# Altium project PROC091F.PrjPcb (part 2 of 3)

## Sheet PROC091F_HD_CONN_PWR_SW.SchDoc: BREAKAWAY_60PIN_CONN
size 431 x 279 mm; Date: Not shown in title block; ApprovedBy: Not shown in title block; CheckedBy: Not shown in title block; Author: Not shown in title block; CompanyName: Not shown in title block; DrawnBy: Antony/Bala; Engineer: Not shown in title block; Organization: Not shown in title block; Address1: Not shown in title block; Address2: Not shown in title block; Address3: Not shown in title block; Address4: Not shown in title block; DocumentNumber: 7; Revision: Use project parameter SCH_Rev; SheetNumber: 7; SheetTotal: 12; PageSetup: Record=PageOptions¦CenterHorizontal=True¦CenterVertical=True¦PrintScale=1.00¦XCorrection=1.00¦YCorrection=1.00¦PrintKind=0¦BorderSize=5000000¦LeftOffset=0¦BottomOffset=0¦Orientation=2¦PaperLength=1000¦PaperWidth=1000¦Scale=100¦PaperSource=15¦PrintQuality=600¦MediaType=1¦DitherType=10¦PaperKind=Letter¦PrintScaleMode=1

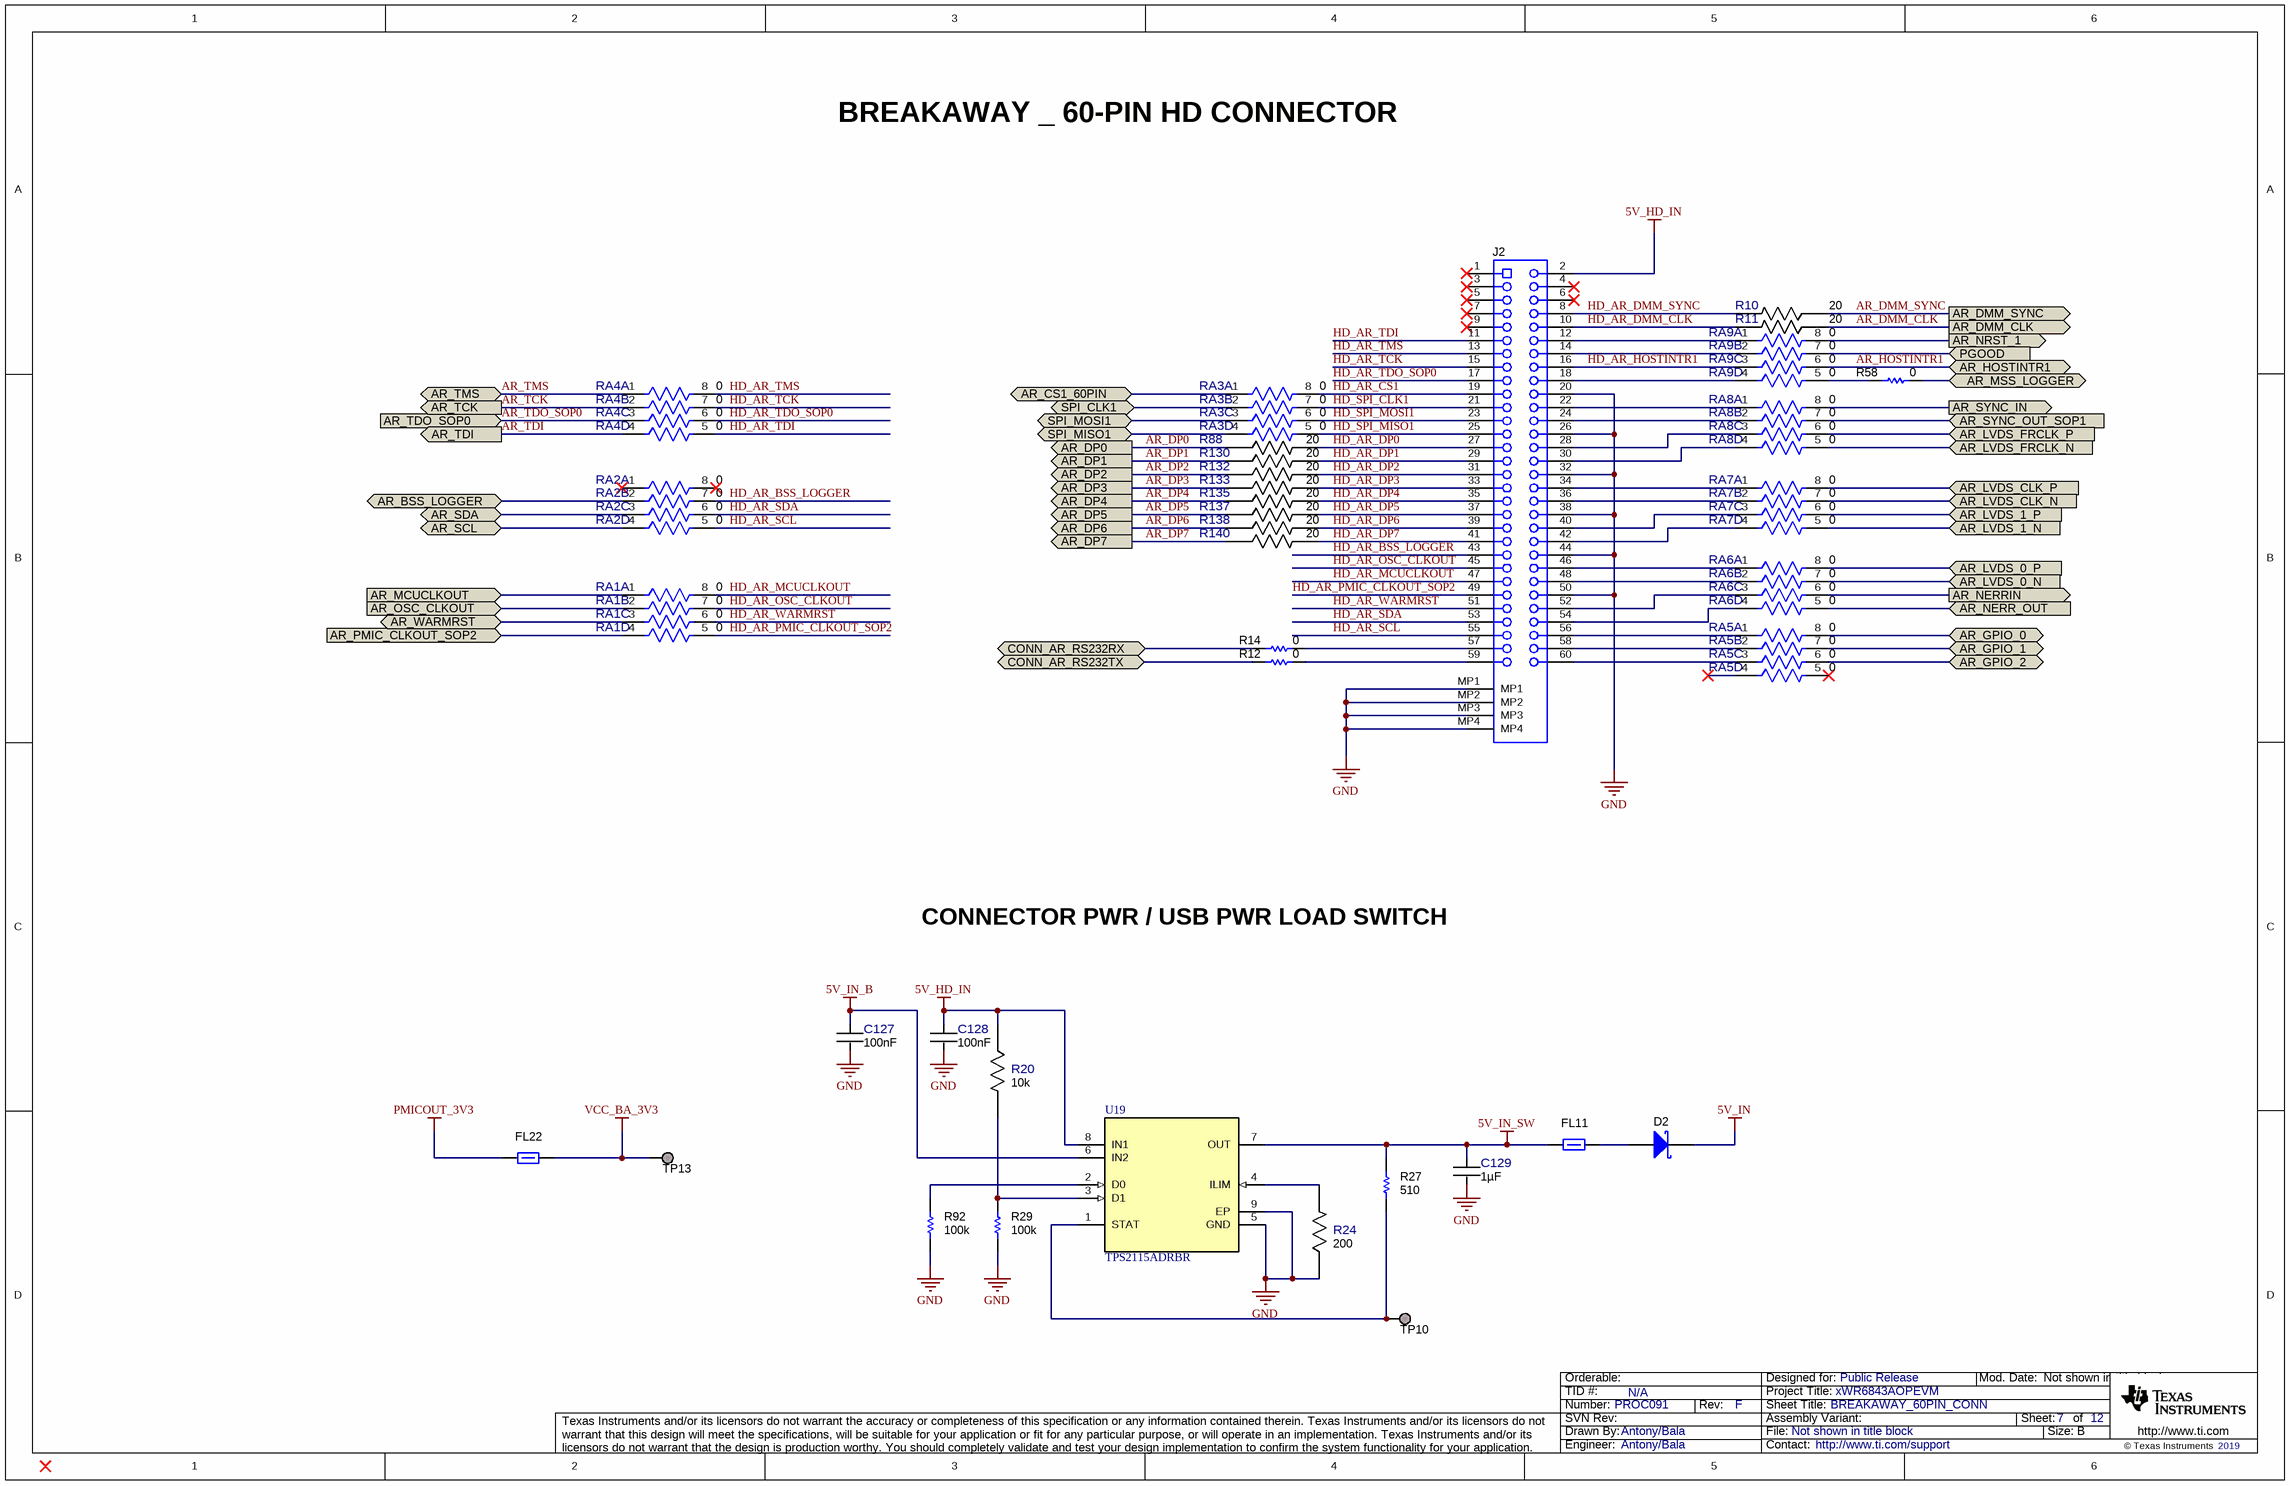
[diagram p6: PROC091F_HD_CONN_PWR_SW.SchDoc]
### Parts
C127  Cap_F: 100nF  [FP-GRM033R6YA104KE14D_0201 (0603 Metric)-IPC_C]  (hidden comment: GRM033R6YA104KE14D)
C128  Cap_F: 100nF  [FP-GRM033R6YA104KE14D_0201 (0603 Metric)-IPC_C]  (hidden comment: GRM033R6YA104KE14D)
C129  Cap_F: 1µF  [FP-CL03A105MO3NRNH_0201-IPC_C]  (hidden comment: CL03A105MO3NRNH)
D2  NSR20F30NXT5G  [DSN2_0603]  (value not drawn)
FL11  BLM15PD300SZ1D  [0402L]  (value not drawn)
FL22  BLM15PD300SZ1D  [0402L]  (value not drawn)
J2  QSH-030-01-L-D-A  [Samtec_QSH-030-01-X-D-A]  (value not drawn)
R10  Res_ohm: 20  [FP-AC0201FR-0720RL_0201-IPC_C]  (hidden comment: AC0201FR-0720RL)
R11  Res_ohm: 20  [FP-AC0201FR-0720RL_0201-IPC_C]  (hidden comment: AC0201FR-0720RL)
R12  Res_ohm: 0  [FP-RC0201JR-070RL_0201 (0603 Metric)-MFG]  (hidden comment: RC0201JR-070RL)
R14  Res_ohm: 0  [FP-RC0201JR-070RL_0201 (0603 Metric)-MFG]  (hidden comment: RC0201JR-070RL)
R20  Res_ohm: 10k  [FP-RR0306P-103-D_0201-IPC_C]  (hidden comment: RR0306P-103-D)
R24  Res_ohm: 200  [FP-CRCW0402200RFKEDHP_0402-IPC_C]  (hidden comment: CRCW0402200RFKEDHP)
R27  value 510  [0201L]  (hidden comment: RC0201JR-07510RL)
R29  value 100k  [0201L]  (hidden comment: CRCW0201100KFKED)
R58  Res_ohm: 0  [FP-RC0201JR-070RL_0201 (0603 Metric)-MFG]  (hidden comment: RC0201JR-070RL)
R88  Res_ohm: 20  [FP-AC0201FR-0720RL_0201-IPC_C]  (hidden comment: AC0201FR-0720RL)
R92  value 100k  [0201L]  (hidden comment: CRCW0201100KFKED)
R130  Res_ohm: 20  [FP-AC0201FR-0720RL_0201-IPC_C]  (hidden comment: AC0201FR-0720RL)
R132  Res_ohm: 20  [FP-AC0201FR-0720RL_0201-IPC_C]  (hidden comment: AC0201FR-0720RL)
R133  Res_ohm: 20  [FP-AC0201FR-0720RL_0201-IPC_C]  (hidden comment: AC0201FR-0720RL)
R135  Res_ohm: 20  [FP-AC0201FR-0720RL_0201-IPC_C]  (hidden comment: AC0201FR-0720RL)
R137  Res_ohm: 20  [FP-AC0201FR-0720RL_0201-IPC_C]  (hidden comment: AC0201FR-0720RL)
R138  Res_ohm: 20  [FP-AC0201FR-0720RL_0201-IPC_C]  (hidden comment: AC0201FR-0720RL)
R140  Res_ohm: 20  [FP-AC0201FR-0720RL_0201-IPC_C]  (hidden comment: AC0201FR-0720RL)
RA1  Res_ohm: 0  [FP-EXB-18VR000X_0502-MFG]  (hidden comment: EXB-18VR000X)  (parts A,B,C,D of 4)
RA2  Res_ohm: 0  [FP-EXB-18VR000X_0502-MFG]  (hidden comment: EXB-18VR000X)  (parts A,B,C,D of 4)
RA3  Res_ohm: 0  [FP-EXB-18VR000X_0502-MFG]  (hidden comment: EXB-18VR000X)  (parts A,B,C,D of 4)
RA4  Res_ohm: 0  [FP-EXB-18VR000X_0502-MFG]  (hidden comment: EXB-18VR000X)  (parts A,B,C,D of 4)
RA5  Res_ohm: 0  [FP-EXB-18VR000X_0502-MFG]  (hidden comment: EXB-18VR000X)  (parts A,B,C,D of 4)
RA6  Res_ohm: 0  [FP-EXB-18VR000X_0502-MFG]  (hidden comment: EXB-18VR000X)  (parts A,B,C,D of 4)
RA7  Res_ohm: 0  [FP-EXB-18VR000X_0502-MFG]  (hidden comment: EXB-18VR000X)  (parts A,B,C,D of 4)
RA8  Res_ohm: 0  [FP-EXB-18VR000X_0502-MFG]  (hidden comment: EXB-18VR000X)  (parts A,B,C,D of 4)
RA9  Res_ohm: 0  [FP-EXB-18VR000X_0502-MFG]  (hidden comment: EXB-18VR000X)  (parts A,B,C,D of 4)
TP10  TESTPOINT  [TP_25MIL-SMT]  (value not drawn)  (no BOM)
TP13  TESTPOINT  [TP_25MIL-SMT]  (value not drawn)  (no BOM)
U19  TPS2115ADRBR  [DRB0008B]

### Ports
AR_BSS_LOGGER (bidir), AR_CS1_60PIN (bidir), AR_DMM_CLK (out), AR_DMM_SYNC (out), AR_DP0 (out), AR_DP1 (out), AR_DP2 (out), AR_DP3 (out), AR_DP4 (out), AR_DP5 (out), AR_DP6 (out), AR_DP7 (out), AR_GPIO_0 (bidir), AR_GPIO_1 (bidir), AR_GPIO_2 (bidir), AR_HOSTINTR1 (bidir), AR_LVDS_0_N (in), AR_LVDS_0_P (in), AR_LVDS_1_N (in), AR_LVDS_1_P (in), AR_LVDS_CLK_N (in), AR_LVDS_CLK_P (in), AR_LVDS_FRCLK_N (in), AR_LVDS_FRCLK_P (in), AR_MCUCLKOUT (in), AR_MSS_LOGGER (bidir), AR_NERR_OUT (in), AR_NERRIN (out), AR_NRST_1 (out), AR_OSC_CLKOUT (in), AR_PMIC_CLKOUT_SOP2 (in), AR_SCL (bidir), AR_SDA (bidir), AR_SYNC_IN (out), AR_SYNC_OUT_SOP1 (in), AR_TCK (out), AR_TDI (out), AR_TDO_SOP0 (in), AR_TMS (bidir), AR_WARMRST (bidir), CONN_AR_RS232RX (bidir), CONN_AR_RS232TX (bidir), PGOOD (in), SPI_CLK1 (bidir), SPI_MISO1 (bidir), SPI_MOSI1 (bidir)

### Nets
5V_HD_IN: C128.1 J2.2 R20.1 U19.8(IN1)
5V_IN: D2.1(K)
5V_IN_B: C127.1 U19.6(IN2)
5V_IN_SW: C129.1 FL11.1 R27.1 U19.7(OUT)
GND: C127.2 C128.2 C129.2 J2.20 J2.26 J2.32 J2.38 J2.44 J2.50 J2.MP1 J2.MP2 J2.MP3 J2.MP4 R24.1 R29.1 R92.2 U19.5(GND) U19.9(EP)
PMICOUT_3V3: FL22.1
VCC_BA_3V3: FL22.2 TP13.1
AR_BSS_LOGGER: RA2.2 ; port AR_BSS_LOGGER
AR_CS1_60PIN: RA3.1 ; port AR_CS1_60PIN
AR_DMM_CLK: R11.1 ; port AR_DMM_CLK
AR_DMM_SYNC: R10.1 ; port AR_DMM_SYNC
AR_DP0: R88.1 ; port AR_DP0
AR_DP1: R130.1 ; port AR_DP1
AR_DP2: R132.1 ; port AR_DP2
AR_DP3: R133.1 ; port AR_DP3
AR_DP4: R135.1 ; port AR_DP4
AR_DP5: R137.1 ; port AR_DP5
AR_DP6: R138.1 ; port AR_DP6
AR_DP7: R140.1 ; port AR_DP7
AR_GPIO_0: RA5.8 ; port AR_GPIO_0
AR_GPIO_1: RA5.7 ; port AR_GPIO_1
AR_GPIO_2: RA5.6 ; port AR_GPIO_2
AR_HOSTINTR1: RA9.6 ; port AR_HOSTINTR1
AR_LVDS_0_N: RA6.7 ; port AR_LVDS_0_N
AR_LVDS_0_P: RA6.8 ; port AR_LVDS_0_P
AR_LVDS_1_N: RA7.5 ; port AR_LVDS_1_N
AR_LVDS_1_P: RA7.6 ; port AR_LVDS_1_P
AR_LVDS_CLK_N: RA7.7 ; port AR_LVDS_CLK_N
AR_LVDS_CLK_P: RA7.8 ; port AR_LVDS_CLK_P
AR_LVDS_FRCLK_N: RA8.5 ; port AR_LVDS_FRCLK_N
AR_LVDS_FRCLK_P: RA8.6 ; port AR_LVDS_FRCLK_P
AR_MCUCLKOUT: RA1.1 ; port AR_MCUCLKOUT
AR_MSS_LOGGER: R58.1 ; port AR_MSS_LOGGER
AR_NERR_OUT: RA6.5 ; port AR_NERR_OUT
AR_NERRIN: RA6.6 ; port AR_NERRIN
AR_NRST_1: RA9.8 ; port AR_NRST_1
AR_OSC_CLKOUT: RA1.2 ; port AR_OSC_CLKOUT
AR_PMIC_CLKOUT_SOP2: RA1.4 ; port AR_PMIC_CLKOUT_SOP2
AR_SCL: RA2.4 ; port AR_SCL
AR_SDA: RA2.3 ; port AR_SDA
AR_SYNC_IN: RA8.8 ; port AR_SYNC_IN
AR_SYNC_OUT_SOP1: RA8.7 ; port AR_SYNC_OUT_SOP1
AR_TCK: RA4.2 ; port AR_TCK
AR_TDI: RA4.4 ; port AR_TDI
AR_TDO_SOP0: RA4.3 ; port AR_TDO_SOP0
AR_TMS: RA4.1 ; port AR_TMS
AR_WARMRST: RA1.3 ; port AR_WARMRST
CONN_AR_RS232RX: R14.2 ; port CONN_AR_RS232RX
CONN_AR_RS232TX: R12.2 ; port CONN_AR_RS232TX
HD_AR_BSS_LOGGER: J2.43 RA2.7
HD_AR_CS1: J2.19 RA3.8
HD_AR_DMM_CLK: J2.10 R11.2
HD_AR_DMM_SYNC: J2.8 R10.2
HD_AR_DP0: J2.27 R88.2
HD_AR_DP1: J2.29 R130.2
HD_AR_DP2: J2.31 R132.2
HD_AR_DP3: J2.33 R133.2
HD_AR_DP4: J2.35 R135.2
HD_AR_DP5: J2.37 R137.2
HD_AR_DP6: J2.39 R138.2
HD_AR_DP7: J2.41 R140.2
HD_AR_HOSTINTR1: J2.16 RA9.3
HD_AR_MCUCLKOUT: J2.47 RA1.8
HD_AR_OSC_CLKOUT: J2.45 RA1.7
HD_AR_PMIC_CLKOUT_SOP2: J2.49 RA1.5
HD_AR_SCL: J2.55 RA2.5
HD_AR_SDA: J2.53 RA2.6
HD_AR_TCK: J2.15 RA4.7
HD_AR_TDI: J2.11 RA4.5
HD_AR_TDO_SOP0: J2.17 RA4.6
HD_AR_TMS: J2.13 RA4.8
HD_AR_WARMRST: J2.51 RA1.6
HD_SPI_CLK1: J2.21 RA3.7
HD_SPI_MISO1: J2.25 RA3.5
HD_SPI_MOSI1: J2.23 RA3.6
PGOOD: RA9.7 ; port PGOOD
SPI_CLK1: RA3.2 ; port SPI_CLK1
SPI_MISO1: RA3.4 ; port SPI_MISO1
SPI_MOSI1: RA3.3 ; port SPI_MOSI1
NetD2_2: D2.2(A) FL11.2
NetJ2_12: J2.12 RA9.1
NetJ2_14: J2.14 RA9.2
NetJ2_18: J2.18 RA9.4
NetJ2_22: J2.22 RA8.1
NetJ2_24: J2.24 RA8.2
NetJ2_28: J2.28 RA8.3
NetJ2_30: J2.30 RA8.4
NetJ2_34: J2.34 RA7.1
NetJ2_36: J2.36 RA7.2
NetJ2_40: J2.40 RA7.3
NetJ2_42: J2.42 RA7.4
NetJ2_46: J2.46 RA6.1
NetJ2_48: J2.48 RA6.2
NetJ2_52: J2.52 RA6.3
NetJ2_54: J2.54 RA6.4
NetJ2_56: J2.56 RA5.1
NetJ2_57: J2.57 R14.1
NetJ2_58: J2.58 RA5.2
NetJ2_59: J2.59 R12.1
NetJ2_60: J2.60 RA5.3
NetR20_2: R20.2 R29.2 U19.3(D1)
NetR24_2: R24.2 U19.4(ILIM)
NetR27_2: R27.2 TP10.1 U19.1(STAT)
NetR58_2: R58.2 RA9.5
NetR92_1: R92.1 U19.2(D0)

Not connected (* = marked no-connect by the designer): J2 1* 3* 4* 5* 6* 7* 9*; RA2 1* 8*; RA5 4* 5*

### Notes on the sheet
- BREAKAWAY _ 60-PIN HD CONNECTOR
- CONNECTOR PWR / USB PWR LOAD SWITCH

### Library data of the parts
C127 C128 = CMP-0086440-1: Cap Ceramic 0.1uF 35V X5R 10% Pad SMD 0201 85C T/R; Manufacturer: Murata Electronics North America; AEC Qualified: No; SizeZ_mm: 0.33mm; Symbol Name: SYM-GRM033R6YA104KE14D; TempCo: 15%
C129 = CMP-0086446-1: 1µF ±20% 16V Ceramic Capacitor X5R 0201; Manufacturer: Samsung Electro-Mechanics; AEC Qualified: No; SizeZ_mm: 0.39mm; Symbol Name: SYM-CL03A105MO3NRNH; TempCo: 15%
D2 = CMP-0028829-2: Diode, Schottky, 30 V, 2 A, 2-XFDFN; Manufacturer: ON Semiconductor; Value2: 0.48V; SizeY_mm: 0.8; Value: 30V; TJmax_C: 150°C; Green_Lifecycle: Not Set; SizeAreaWB_mm2: 4.68; Value1: 2A; SizeArea_mm2: 1.28; Green_REACh: Incomplete; AEC Category: Q101; SizeZ_mm: 0.31; Vf_V: 480mV; AEC Qualified: N; SizeX_mm: 1.6
FL11 FL22 = CMP-0078934-1: Inductor, Ferrite Bead, Ferrite, 2.2 A, 0.035 ohm, AEC-Q200 Grade 1, SMD; Manufacturer: MuRata; AEC Category: Q200; AEC Grade: 1; AEC Qualified: Y; DCR_ohm: 0.035; Imax_A: 2.2A; SizeArea_mm2: 0.5; SizeAreaWB_mm2: 3; SizeZ_mm: 0.6
J2 = CMP-0075524-1: Receptacle, 0.5 mm, 30x2, Gold, TH; Manufacturer: Samtec; Pitch_mm: 0.5; Gender: Female; Green_REACh: Passed; CT: False; Shrouded: N; RowSpacing_mm: 5.73; Green_Lifecycle: Active; Row_Count: 2
R10 R11 R88 R130 R132 R133 R135 R137 R138 R140 = CMP-0087185-1: RES SMD 20 OHM 1% 1/20W 0201; Manufacturer: Yageo; AEC Grade: Grade 0; AEC Qualified: Yes; Power_W: 50mW; SizeZ_mm: 0.26mm; Symbol Name: SYM-AC0201FR-0720RL; TempCo: 200ppm/°C; VDC_V: 25V
R12 R14 R58 = CMP-0086442-2: RES SMD 0 OHM JUMPER 1/20W 0201; Manufacturer: Yageo; AEC Qualified: No; Power_W: 50mW; SizeZ_mm: 0.26mm; TempCo: 200ppm/°C; Tolerance_%: 5%; VDC_V: 25V
R20 = CMP-0088002-1: 10 kOhms ±0.5% 0.05W, 1/20W Chip Resistor 0201 (0603 Metric)  Thin Film; Manufacturer: Susumu; AEC Qualified: No; Power_W: 50mW; SizeZ_mm: 0.26mm; Symbol Name: SYM-RR0306P-103-D; TempCo: 25ppm/°C; VDC_V: 15V
R24 = CMP-0087183-1: RES SMD 200 OHM 1% 1/5W 0402; Manufacturer: Vishay Dale; AEC Grade: Grade 0; AEC Qualified: Yes; Power_W: 200mW; SizeZ_mm: 0.4mm; Symbol Name: SYM-CRCW0402200RFKEDHP; TempCo: 100ppm/°C; VDC_V: 50V
R27 = CMP-0027137-1: RES, 510, 5%, 0.05 W, 0201; Manufacturer: Yageo America; AEC Category: Q200; AEC Qualified: N; EIA_Code: E24; Power_W: 50mW; SizeArea_mm2: 0.18; SizeX_mm: 0.6; SizeY_mm: 0.3; SizeZ_mm: 0.26; TempCo: 200 ppm/C; U/M: EA; Value2: 0.05W; Value_Code: 510R; VDC_V: 25V
R29 R92 = CMP-0027261-3: RES, 100 k, 1%, 0.05 W, 0201; Manufacturer: Vishay-Dale; AEC Category: Q200; AEC Qualified: N; EIA_Code: E96; Power_W: 50mW; SizeArea_mm2: 0.18; SizeX_mm: 0.6; SizeY_mm: 0.3; SizeZ_mm: 0.26; TempCo: 100 ppm/C; Value2: 0.05W; VDC_V: 30V
RA1-RA9 = CMP-0087186-1: RES ARRAY 4 RES ZERO OHM 0502; Manufacturer: Panasonic Electronic Components; AEC Qualified: No; Power_W: 100mW; SizeZ_mm: 0.45mm; TempCo: -200/+600ppm/°C; Tolerance_%: 5%; VDC_V: 12.5V
TP10 TP13 = CMP-0078143-3: TEST POINT.  No entry in BOM.
U19 = CMP-0043358-3: Dual In / Single Out Autoswitching Power Mux, 2.8 to 5.5 V, -40 to 85 degC, 8-pin SON (DRB), Green (RoHS & no Sb/Br); Manufacturer: Texas Instruments; AEC Category: Q200; AEC Qualified: N; CompType: IC; IN1, IN2 Input Voltage(Max)(V): 5.5; IN1, IN2 Input Voltage(Min)(V): 2.8; IN1 Output Current(Max)(A): 1.25; IN1 rDS(on)(Typ)(mOhm): 84; IN2 rDS(on)(Typ)(Ohms): 0.084; Number of Inputs: 2; SizeArea_mm2: 9.0; SizeAreaWB_mm2: 16.0; SizeX_mm: 3.0; SizeZ_mm: 1.0; SubFamily: Power Multiplexer (MUX)

## Sheet PROC091F_RST_GPIOs_I2C.SchDoc: BREAKAWAY_SECTION2
size 431 x 279 mm; Date: Not shown in title block; ApprovedBy: Not shown in title block; CheckedBy: Not shown in title block; Author: Not shown in title block; CompanyName: Not shown in title block; DrawnBy: Antony/Bala; Engineer: Not shown in title block; Organization: Not shown in title block; Address1: Not shown in title block; Address2: Not shown in title block; Address3: Not shown in title block; Address4: Not shown in title block; DocumentNumber: 8; Revision: Use project parameter SCH_Rev; SheetNumber: 8; SheetTotal: 12; PageSetup: Record=PageOptions¦CenterHorizontal=True¦CenterVertical=True¦PrintScale=1.00¦XCorrection=1.00¦YCorrection=1.00¦PrintKind=0¦BorderSize=5000000¦LeftOffset=0¦BottomOffset=0¦Orientation=2¦PaperLength=1000¦PaperWidth=1000¦Scale=100¦PaperSource=15¦PrintQuality=600¦MediaType=1¦DitherType=10¦PaperKind=Letter¦PrintScaleMode=1

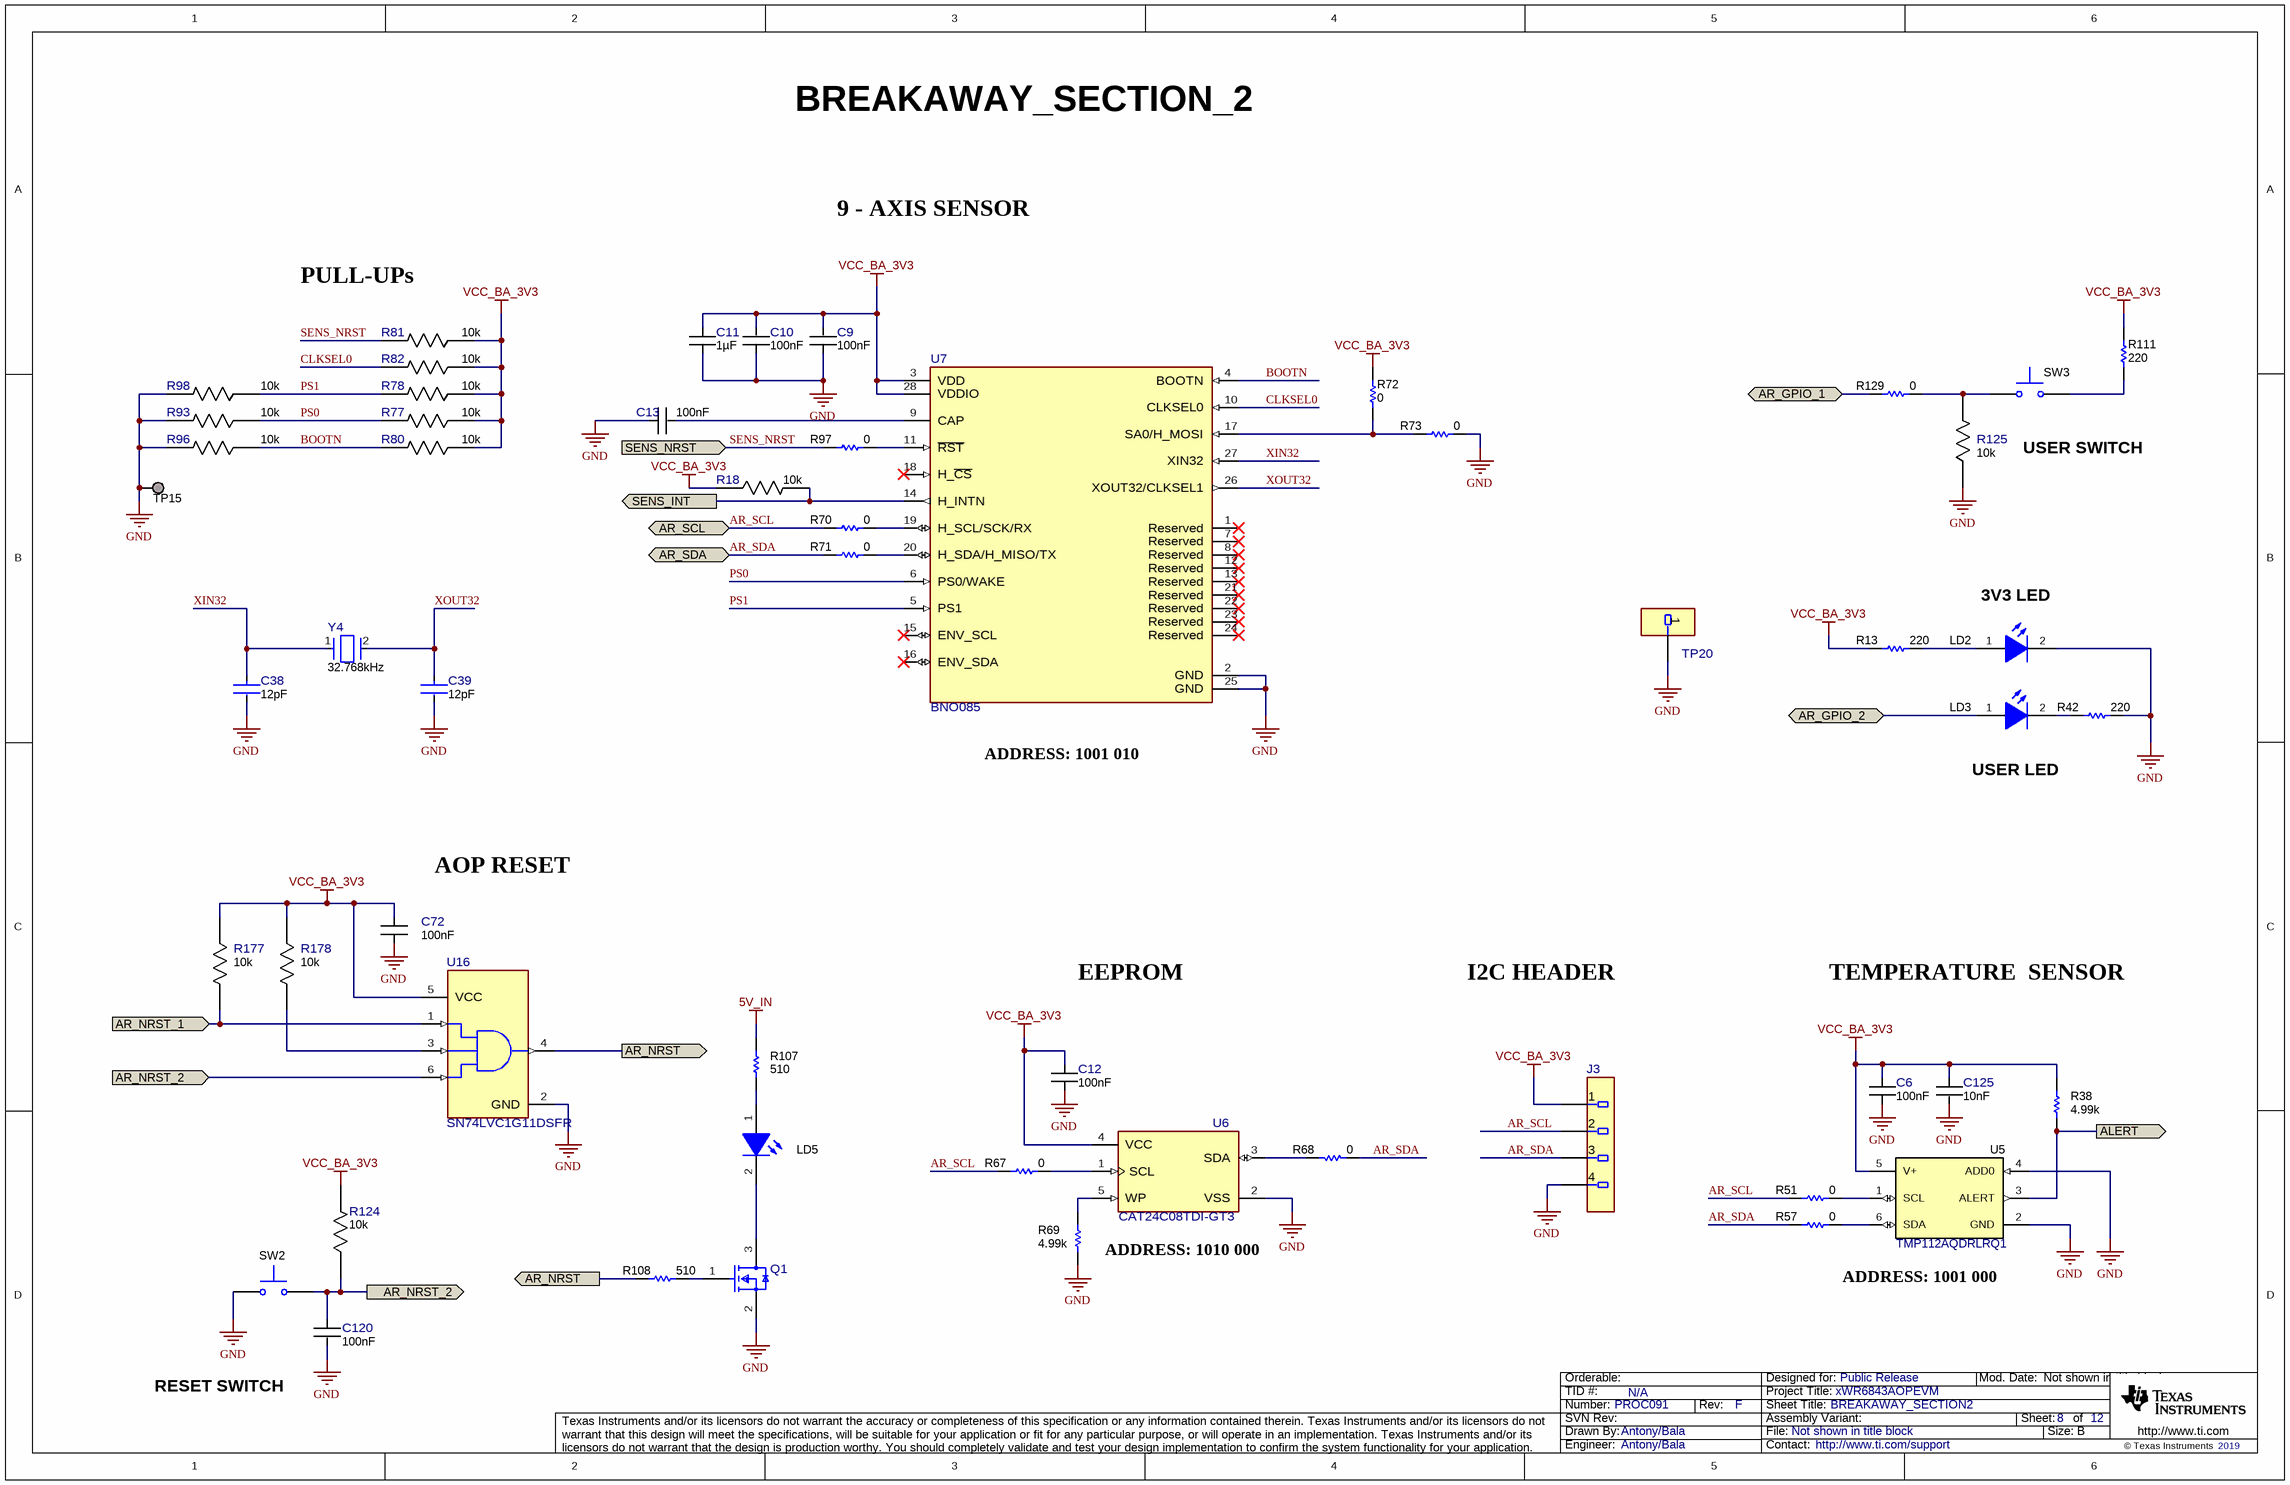
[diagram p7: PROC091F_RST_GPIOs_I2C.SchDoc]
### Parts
C6  Cap_F: 100nF  [FP-GRM033R6YA104KE14D_0201 (0603 Metric)-IPC_C]  (hidden comment: GRM033R6YA104KE14D)
C9  Cap_F: 100nF  [FP-GRM033R6YA104KE14D_0201 (0603 Metric)-IPC_C]  (hidden comment: GRM033R6YA104KE14D)
C10  Cap_F: 100nF  [FP-GRM033R6YA104KE14D_0201 (0603 Metric)-IPC_C]  (hidden comment: GRM033R6YA104KE14D)
C11  Cap_F: 1µF  [FP-CL03A105MO3NRNH_0201-IPC_C]  (hidden comment: CL03A105MO3NRNH)
C12  Cap_F: 100nF  [FP-GRM033R6YA104KE14D_0201 (0603 Metric)-IPC_C]  (hidden comment: GRM033R6YA104KE14D)
C13  Cap_F: 100nF  [FP-GRM033R6YA104KE14D_0201 (0603 Metric)-IPC_C]  (hidden comment: GRM033R6YA104KE14D)
C38  Cap_F: 12pF  [FP-250R05L120JV4T_0201-IPC_C]  (hidden comment: 250R05L120JV4T)
C39  Cap_F: 12pF  [FP-250R05L120JV4T_0201-IPC_C]  (hidden comment: 250R05L120JV4T)
C72  Cap_F: 100nF  [FP-GRM033R6YA104KE14D_0201 (0603 Metric)-IPC_C]  (hidden comment: GRM033R6YA104KE14D)
C120  Cap_F: 100nF  [FP-GRM033R6YA104KE14D_0201 (0603 Metric)-IPC_C]  (hidden comment: GRM033R6YA104KE14D)
C125  Cap_F: 10nF  [FP-CL03A103KA3NNNC_0201-IPC_C]  (hidden comment: CL03A103KA3NNNC)
J3  M50-3930442  [FP-M50-3930442_HDR4-Recommended_Land_Pattern]  (value not drawn)
LD2  APHHS1005CGCK  [APHHS1005_Green]  (value not drawn)
LD3  APHHS1005CGCK  [APHHS1005_Green]  (value not drawn)
LD5  APHHS1005CGCK  [APHHS1005_Green]  (value not drawn)
Q1  BSS123-7-F  [FP-BSS123-7-F_SOT23-IPC_C]  (value not drawn)
R13  value 220  [0201L]  (hidden comment: RC0201JR-07220RL)
R18  Res_ohm: 10k  [FP-RR0306P-103-D_0201-IPC_C]  (hidden comment: RR0306P-103-D)
R38  value 4.99k  [0201L]  (hidden comment: RC0201FR-074K99L)
R42  value 220  [0201L]  (hidden comment: RC0201JR-07220RL)
R51  Res_ohm: 0  [FP-RC0201JR-070RL_0201 (0603 Metric)-MFG]  (hidden comment: RC0201JR-070RL)
R57  Res_ohm: 0  [FP-RC0201JR-070RL_0201 (0603 Metric)-MFG]  (hidden comment: RC0201JR-070RL)
R67  Res_ohm: 0  [FP-RC0201JR-070RL_0201 (0603 Metric)-MFG]  (hidden comment: RC0201JR-070RL)
R68  Res_ohm: 0  [FP-RC0201JR-070RL_0201 (0603 Metric)-MFG]  (hidden comment: RC0201JR-070RL)
R69  value 4.99k  [0201L]  (hidden comment: RC0201FR-074K99L)
R70  Res_ohm: 0  [FP-RC0201JR-070RL_0201 (0603 Metric)-MFG]  (hidden comment: RC0201JR-070RL)
R71  Res_ohm: 0  [FP-RC0201JR-070RL_0201 (0603 Metric)-MFG]  (hidden comment: RC0201JR-070RL)
R72  Res_ohm: 0  [FP-RC0201JR-070RL_0201 (0603 Metric)-IPC_C]  (hidden comment: RC0201JR-070RL)
R73  Res_ohm: 0  [FP-RC0201JR-070RL_0201 (0603 Metric)-IPC_C]  (hidden comment: RC0201JR-070RL)
R77  Res_ohm: 10k  [FP-RR0306P-103-D_0201-IPC_C]  (hidden comment: RR0306P-103-D)
R78  Res_ohm: 10k  [FP-RR0306P-103-D_0201-IPC_C]  (hidden comment: RR0306P-103-D)
R80  Res_ohm: 10k  [FP-RR0306P-103-D_0201-IPC_C]  (hidden comment: RR0306P-103-D)
R81  Res_ohm: 10k  [FP-RR0306P-103-D_0201-IPC_C]  (hidden comment: RR0306P-103-D)
R82  Res_ohm: 10k  [FP-RR0306P-103-D_0201-IPC_C]  (hidden comment: RR0306P-103-D)
R93  Res_ohm: 10k  [FP-RR0306P-103-D_0201-IPC_C]  (hidden comment: RR0306P-103-D)
R96  Res_ohm: 10k  [FP-RR0306P-103-D_0201-IPC_C]  (hidden comment: RR0306P-103-D)
R97  Res_ohm: 0  [FP-RC0201JR-070RL_0201 (0603 Metric)-IPC_C]  (hidden comment: RC0201JR-070RL)
R98  Res_ohm: 10k  [FP-RR0306P-103-D_0201-IPC_C]  (hidden comment: RR0306P-103-D)
R107  value 510  [0201L]  (hidden comment: RC0201JR-07510RL)
R108  value 510  [0201L]  (hidden comment: RC0201JR-07510RL)
R111  value 220  [0201L]  (hidden comment: RC0201JR-07220RL)
R124  Res_ohm: 10k  [FP-RR0306P-103-D_0201-IPC_C]  (hidden comment: RR0306P-103-D)
R125  Res_ohm: 10k  [FP-RR0306P-103-D_0201-IPC_C]  (hidden comment: RR0306P-103-D)
R129  Res_ohm: 0  [FP-RC0201JR-070RL_0201 (0603 Metric)-IPC_C]  (hidden comment: RC0201JR-070RL)
R177  Res_ohm: 10k  [FP-RR0306P-103-D_0201-IPC_C]  (hidden comment: RR0306P-103-D)
R178  Res_ohm: 10k  [FP-RR0306P-103-D_0201-IPC_C]  (hidden comment: RR0306P-103-D)
SW2  B3U-1000P  [SW_B3U-1000P]  (value not drawn)
SW3  B3U-1000P  [SW_B3U-1000P]  (value not drawn)
TP15  TESTPOINT  [TP_25MIL-SMT]  (value not drawn)  (no BOM)
TP20  4953  [FP-4953_HDR1-MFG]  (value not drawn)
U5  TMP112AQDRLRQ1  [DRL0006A]
U6  CAT24C08TDI-GT3  [FP-CAT24C08TDI-GT3_TSOT-23-5-IPC_A]
U7  BNO085  [FP-BNO085_LGA28-MFG]
U16  SN74LVC1G11DSFR  [DSF0006A-MFG]
Y4  Frequency_Fixed: 32.768kHz  [FP-ABS05W-32.768KHZ-D-2-T_XTAL_SMT_1MM6_1MM0-MFG]  (hidden comment: ABS05W-32.768KHZ-D-2-T)

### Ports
ALERT (out), AR_GPIO_1 (bidir), AR_GPIO_2 (bidir), AR_NRST (out), AR_NRST_1 (in), AR_NRST_2 (in), AR_NRST_2 (out), AR_SCL (bidir), AR_SDA (bidir), SENS_INT (out), SENS_NRST (in)

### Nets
5V_IN: R107.1
GND: C6.1 C9.1 C10.1 C11.2 C12.1 C13.1 C38.2 C39.2 C72.1 C120.2 C125.2 J3.4 LD2.2(K) Q1.2(S) R42.2 R69.1 R73.1 R93.2 R96.2 R98.2 R125.1 SW2.2 TP15.1 TP20.1 U5.2(GND) U5.4(ADD0) U6.2(VSS) U7.2(GND) U7.25(GND) U16.2(GND)
VCC_BA_3V3: C6.2 C9.2 C10.2 C11.1 C12.2 C72.2 C125.1 J3.1 R13.1 R18.1 R38.2 R72.1 R77.1 R78.1 R80.1 R81.1 R82.1 R111.2 R124.2 R177.1 R178.1 U5.5(V+) U6.4(VCC) U7.3(VDD) U7.28(VDDIO) U16.5(VCC)
ALERT: R38.1 U5.3(ALERT) ; port ALERT
AR_GPIO_1: R129.2 ; port AR_GPIO_1
AR_GPIO_2: LD3.1(A) ; port AR_GPIO_2
AR_NRST: R108.1 U16.4(Y) ; port AR_NRST
AR_NRST_1: R177.2 U16.1(A) ; port AR_NRST_1
AR_NRST_2: C120.1 R124.1 SW2.1 U16.6(C) ; port AR_NRST_2
AR_SCL: J3.2 R51.1 R67.1 R70.2 ; port AR_SCL
AR_SDA: J3.3 R57.1 R68.1 R71.2 ; port AR_SDA
BOOTN: R80.2 R96.1 U7.4(BOOTN)
CLKSEL0: R82.2 U7.10(CLKSEL0)
PS0: R77.2 R93.1 U7.6(PS0/WAKE)
PS1: R78.2 R98.1 U7.5(PS1)
SENS_INT: R18.2 U7.14(H_INTN) ; port SENS_INT
SENS_NRST: R81.2 R97.2 ; port SENS_NRST
XIN32: C38.1 U7.27(XIN32) Y4.1
XOUT32: C39.1 U7.26(XOUT32/CLKSEL1) Y4.2
NetC13_2: C13.2 U7.9(CAP)
NetLD2_1: LD2.1(A) R13.2
NetLD3_2: LD3.2(K) R42.1
NetLD5_1: LD5.1(A) R107.2
NetLD5_2: LD5.2(K) Q1.3(D)
NetQ1_1: Q1.1(G) R108.2
NetR51_2: R51.2 U5.1(SCL)
NetR57_2: R57.2 U5.6(SDA)
NetR67_2: R67.2 U6.1(SCL)
NetR68_2: R68.2 U6.3(SDA)
NetR69_2: R69.2 U6.5(WP)
NetR70_1: R70.1 U7.19(H_SCL/SCK/RX)
NetR71_1: R71.1 U7.20(H_SDA/H_MISO/TX)
NetR72_2: R72.2 R73.2 U7.17(SA0/H_MOSI)
NetR97_1: R97.1 U7.11(~{RST})
NetR111_1: R111.1 SW3.2
NetR125_2: R125.2 R129.1 SW3.1
NetR178_2: R178.2 U16.3(B)

Not connected (* = marked no-connect by the designer): U7 1(Reserved)* 7(Reserved)* 8(Reserved)* 12(Reserved)* 13(Reserved)* 15(ENV_SCL)* 16(ENV_SDA)* 18(H_~{CS})* 21(Reserved)* 22(Reserved)* 23(Reserved)* 24(Reserved)*

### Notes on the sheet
- BREAKAWAY_SECTION_2
- 9 - AXIS SENSOR
- PULL-UPs
- (near SW3) USER SWITCH
- (near LD2) 3V3 LED
- ADDRESS: 1001 010
- USER LED
- AOP RESET
- EEPROM
- I2C HEADER
- TEMPERATURE  SENSOR
- ADDRESS: 1010 000
- ADDRESS: 1001 000
- RESET SWITCH

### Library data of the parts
C6 C9 C10 C12 C13 C72 C120 = CMP-0086440-1: as C127 on sheet PROC091F_HD_CONN_PWR_SW
C11 = CMP-0086446-1: as C129 on sheet PROC091F_HD_CONN_PWR_SW
C38 C39 = CMP-0087190-1: CAP CER 12PF 25V C0G/NP0 0201; Manufacturer: Johanson Technology Inc.; AEC Grade: Grade 1; AEC Qualified: Yes; SizeZ_mm: 0.33mm; Symbol Name: SYM-250R05L120JV4T; TempCo: 30ppm/°C; Tolerance_%: 5%
C125 = CMP-0086445-1: CAP CER 10000PF 25V X5R 0201; Manufacturer: Samsung Electro-Mechanics America, Inc; AEC Qualified: No; SizeZ_mm: 0.33mm; Symbol Name: SYM-CL03A103KA3NNNC; TempCo: 15%; Tolerance_%: 10%
J3 = CMP-0087187-1: CONN HDR 1.27MM R/A AU 4POS; Manufacturer: Harwin Inc.; ContactFinish: Gold; Current_A: 1A; Row_Count: 1
LD2 LD3 LD5 = CMP-0067682-2: LED, Green, SMD; Manufacturer: Kingbright; Angle: 120.0; Power_TotalModule: 75mW; SizeZ_mm: 0.6; Vf_V: 2.1V; Vr_V: 5V; Io_A: 20mA; Ir_A: 10µA; SizeArea_mm2: 0.5; SizeAreaWB_mm2: 3.0; SizeX_mm: 1.0; Tjmax_C: 85°C; Value1: 0.075W
Q1 = CMP-0087176-1: MOSFET N-CH 100V 170MA SOT23-3; Manufacturer: Diodes Incorporated; AEC Qualified: No; ChMode: False; Rdson45_ohm: 6; SizeZ_mm: 1.1mm; Vgs_V: 20V
R13 R42 R111 = CMP-0027072-1: RES, 220, 5%, 0.05 W, 0201; Manufacturer: Yageo America; AEC Category: Q200; AEC Qualified: N; EIA_Code: E24; Power_W: 50mW; SizeArea_mm2: 0.18; SizeX_mm: 0.6; SizeY_mm: 0.3; SizeZ_mm: 0.26; TempCo: 200 ppm/C; U/M: EA; Value2: 0.05W; Value_Code: 220R; VDC_V: 25V
R18 R77 R78 R80-R82 R93 R96 R98 R124 R125 R177 R178 = CMP-0088002-1: as R20 on sheet PROC091F_HD_CONN_PWR_SW
R38 R69 = CMP-0027745-1: RES, 4.99 k, 1%, 0.05 W, 0201; Manufacturer: Yageo America; AEC Category: Q200; AEC Qualified: N; EIA_Code: E96; Power_W: 50mW; SizeArea_mm2: 0.18; SizeX_mm: 0.6; SizeY_mm: 0.3; SizeZ_mm: 0.26; TempCo: 200 ppm/C; U/M: EA; Value2: 0.05W; Value_Code: 4k99; VDC_V: 25V
R51 R57 R67 R68 R70-R73 R97 R129 = CMP-0086442-2: as R12 on sheet PROC091F_HD_CONN_PWR_SW
R107 R108 = CMP-0027137-1: as R27 on sheet PROC091F_HD_CONN_PWR_SW
SW2 SW3 = CMP-0002150-2: SWITCH TACTILE SPST-NO 0.05A 12V; Manufacturer: Omron Electronic Components; CurrentRating_mA: 50A; PositionCount: 1; SwitchFunction: Off-Mom
TP15 = CMP-0078143-3: TEST POINT.  No entry in BOM.
TP20 = CMP-0086474-1: PC Test Point, Loop Brass, Tin Plating 0.047" (1.19mm) Hole Diameter Mounting Type; Manufacturer: Keystone Electronics
U5 = CMP-0067398-2: Automotive Grade, 1.4V-Capable +/-0.5degC Temperature Sensor with Alert Function and I2C/SMBus, DRL0006A (SOT-OTHER-6); Alternate Manufacturer: Texas Instruments; CompType: IC; SizeArea_mm2: 2.56; SizeAreaWB_mm2: 6.76; SizeX_mm: 1.6; SizeZ_mm: 0.6; U/M: EA
U6 = CMP-0087170-1: 8KB I2C SER EEPROM TSOT 23; Manufacturer: ON Semiconductor; SizeZ_mm: 1mm
U7 = CMP-0087171-1: IMU ACCEL/GYRO/MAG I2C 32BIT; Manufacturer: Hillcrest Laboratories, Inc.; SizeZ_mm: 1.18mm
U16 = CMP-0087998-2: AND Gate IC 1 Channel  6-SON (1x1); Manufacturer: Texas Instruments; TJmax_C: +150°C; PositionCount: 1; Number Of Inputs: 3; SizeZ_mm: 0.4mm; TaMax_C: +125°C; Max Supply Voltage: 5.5V; Min Supply Voltage: 1.65V; Standoff Height: 0mm; AEC Qualified: No; TaMin_C: -40°C; AEC Category: Q200
Y4 = CMP-0088006-1: CRYSTAL 32.768KHZ 4PF SMD; Manufacturer: Abracon LLC; AEC Qualified: No; Frequency Tolerance: 20ppm; SizeZ_mm: 0.5mm

## Sheet PROC091F_BT_DISPLAY.SchDoc: BREAKAWAY_SECTION3
size 431 x 279 mm; Date: Not shown in title block; ApprovedBy: Not shown in title block; CheckedBy: Not shown in title block; Author: Not shown in title block; CompanyName: Not shown in title block; DrawnBy: Antony/Bala; Engineer: Not shown in title block; Organization: Not shown in title block; Address1: Not shown in title block; Address2: Not shown in title block; Address3: Not shown in title block; Address4: Not shown in title block; DocumentNumber: 9; Revision: Use project parameter SCH_Rev; SheetNumber: 9; SheetTotal: 12; PageSetup: Record=PageOptions¦CenterHorizontal=True¦CenterVertical=True¦PrintScale=1.00¦XCorrection=1.00¦YCorrection=1.00¦PrintKind=0¦BorderSize=5000000¦LeftOffset=0¦BottomOffset=0¦Orientation=2¦PaperLength=1000¦PaperWidth=1000¦Scale=100¦PaperSource=15¦PrintQuality=600¦MediaType=1¦DitherType=10¦PaperKind=Letter¦PrintScaleMode=1

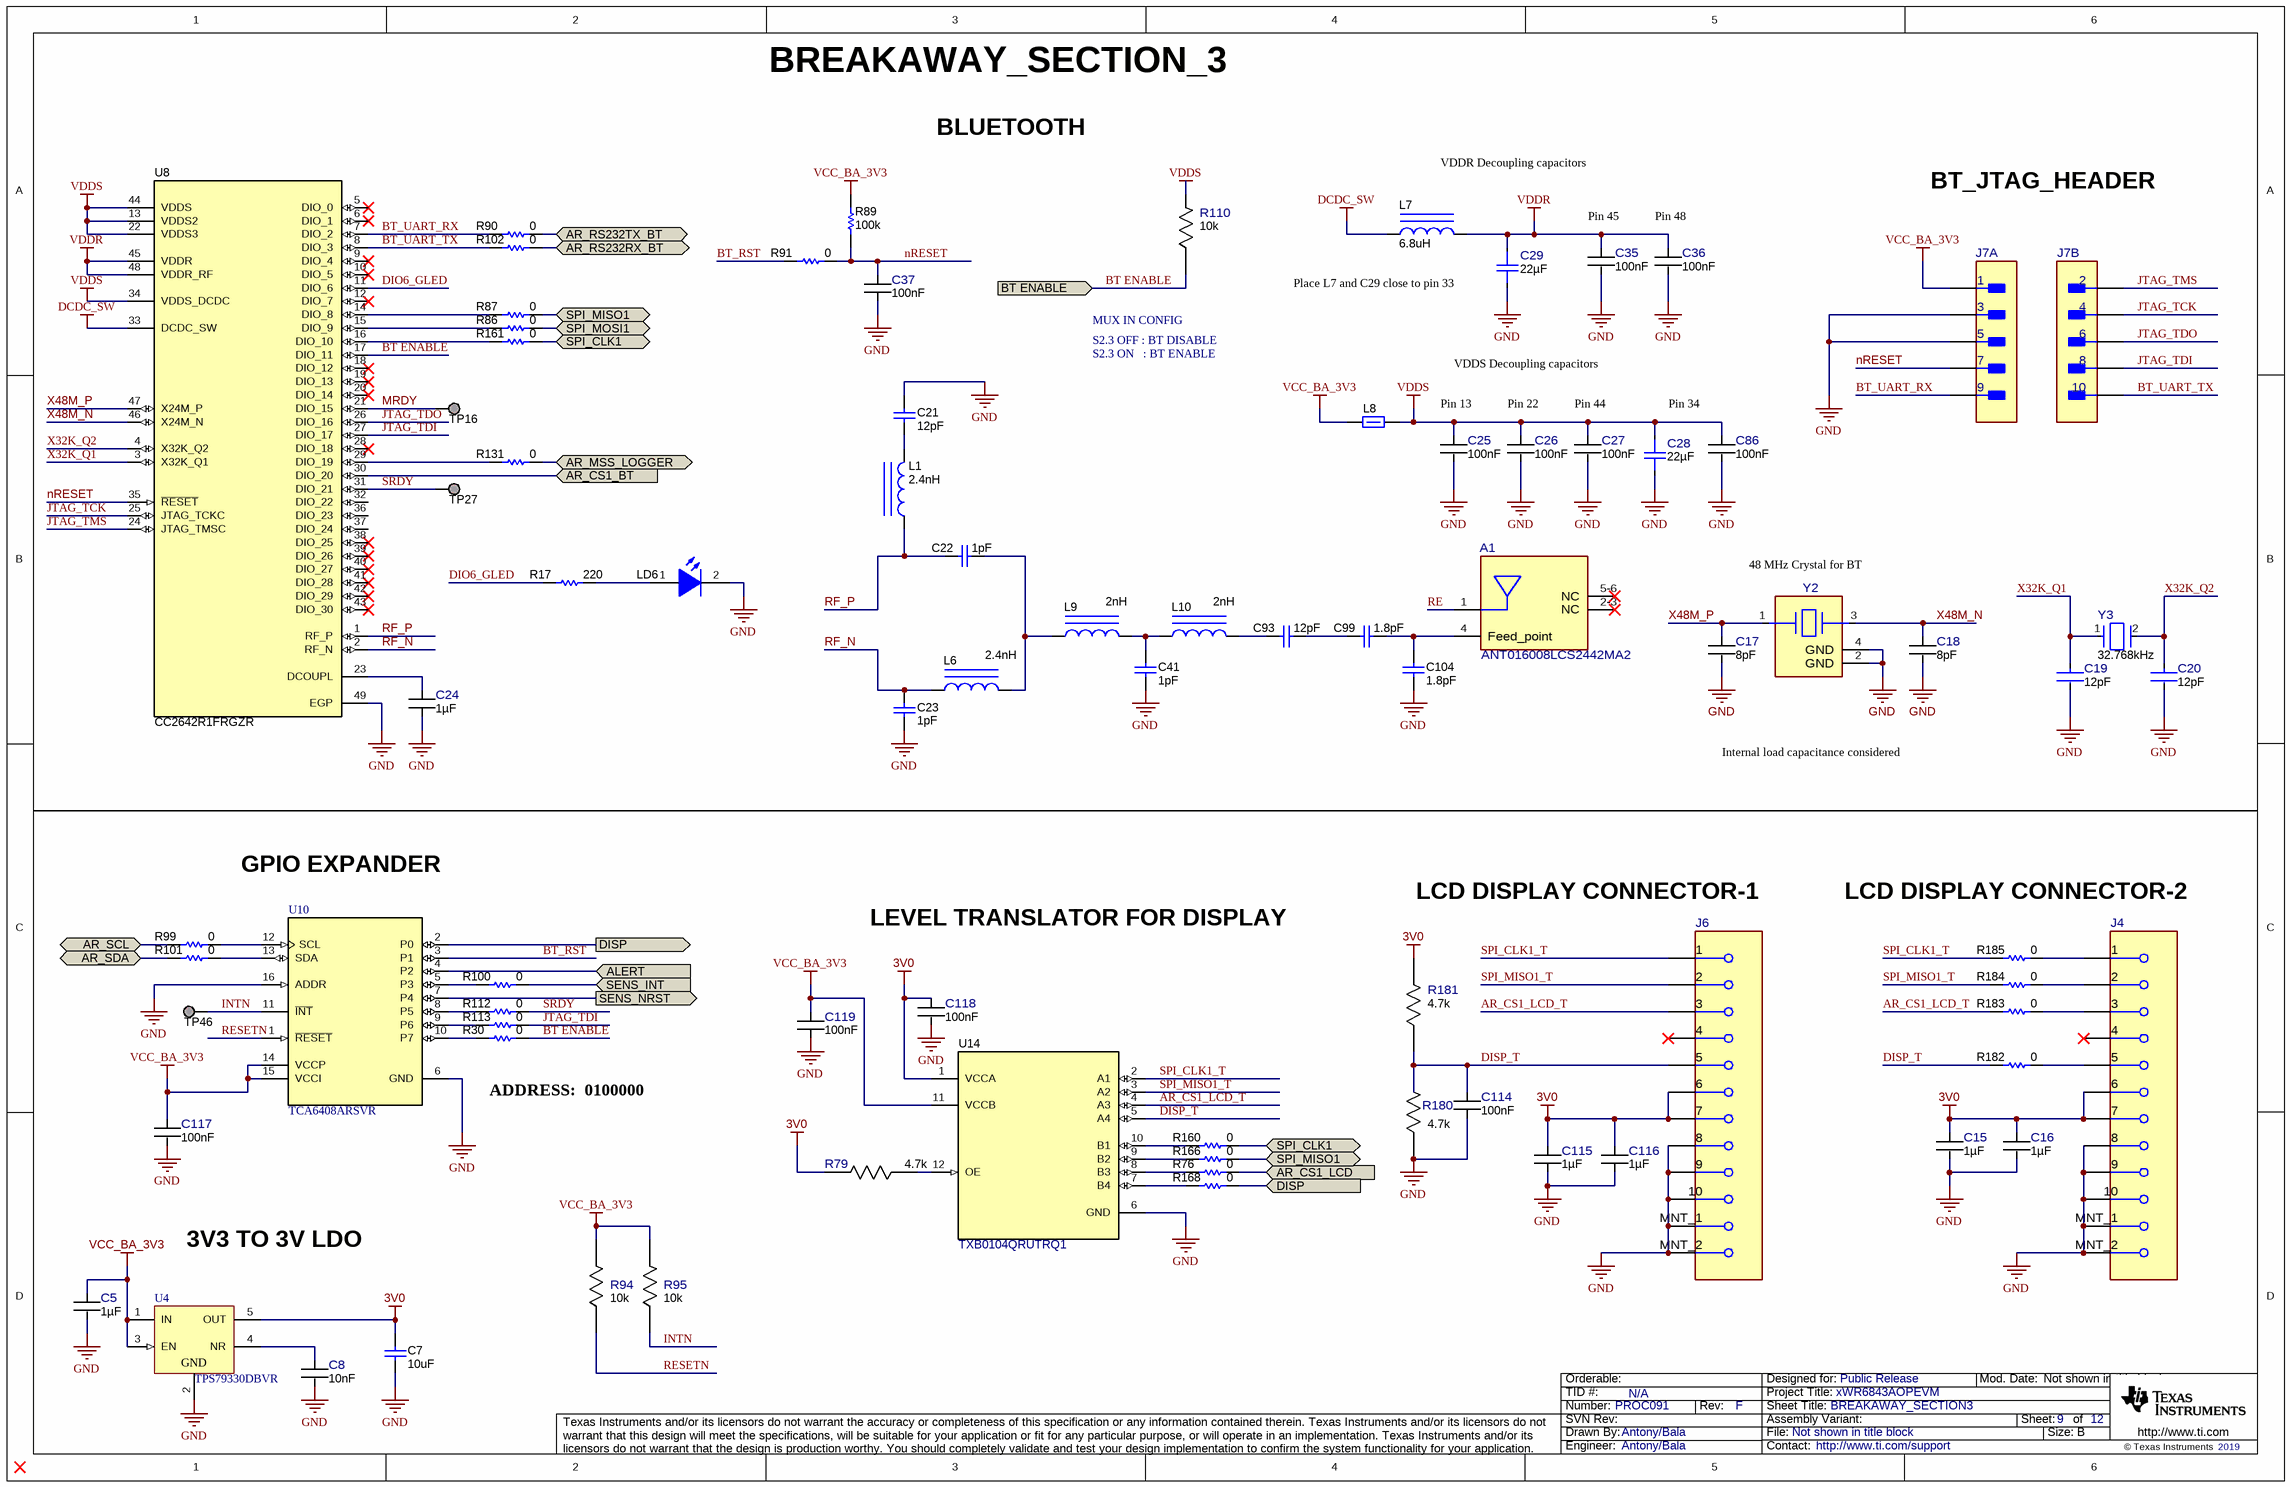
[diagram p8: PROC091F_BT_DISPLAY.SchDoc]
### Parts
A1  ANT016008LCS2442MA2  [FP-ANT016008LCS2442MA2_SMT_ANT-0]
C5  Cap_F: 1µF  [FP-CL03A105MO3NRNH_0201-IPC_C]  (hidden comment: CL03A105MO3NRNH)
C7  value 10uF  [0402_070]  (hidden comment: CL05A106MP5NUNC)
C8  Cap_F: 10nF  [FP-CL03A103KA3NNNC_0201-IPC_C]  (hidden comment: CL03A103KA3NNNC)
C15  Cap_F: 1µF  [FP-CL03A105MO3NRNH_0201-IPC_C]  (hidden comment: CL03A105MO3NRNH)
C16  Cap_F: 1µF  [FP-CL03A105MO3NRNH_0201-IPC_C]  (hidden comment: CL03A105MO3NRNH)
C17  Cap_F: 8pF  [FP-GRM0335C1H8R0BA01D_0201 (0603 metric)-IPC_C]  (hidden comment: GRM0335C1H8R0BA01D)
C18  Cap_F: 8pF  [FP-GRM0335C1H8R0BA01D_0201 (0603 metric)-IPC_C]  (hidden comment: GRM0335C1H8R0BA01D)
C19  Cap_F: 12pF  [FP-250R05L120JV4T_0201-IPC_C]  (hidden comment: 250R05L120JV4T)
C20  Cap_F: 12pF  [FP-250R05L120JV4T_0201-IPC_C]  (hidden comment: 250R05L120JV4T)
C21  ValueDisplayed: 12pF  [0402L]  (hidden comment: CL05C120JB5NNNC)
C22  ValueDisplayed: 1pF  [0402L]  (hidden comment: GCM1555C1H1R0CA16D)
C23  ValueDisplayed: 1pF  [0402L]  (hidden comment: GCM1555C1H1R0CA16D)
C24  Cap_F: 1µF  [FP-CL03A105MO3NRNH_0201-IPC_C]  (hidden comment: CL03A105MO3NRNH)
C25  Cap_F: 100nF  [FP-GRM033R6YA104KE14D_0201 (0603 Metric)-IPC_C]  (hidden comment: GRM033R6YA104KE14D)
C26  Cap_F: 100nF  [FP-GRM033R6YA104KE14D_0201 (0603 Metric)-IPC_C]  (hidden comment: GRM033R6YA104KE14D)
C27  Cap_F: 100nF  [FP-GRM033R6YA104KE14D_0201 (0603 Metric)-IPC_C]  (hidden comment: GRM033R6YA104KE14D)
C28  Cap_F: 22µF  [FP-CL05A226MQ5N6J8_0402-IPC_C]  (hidden comment: CL05A226MQ5N6J8)
C29  Cap_F: 22µF  [FP-CL05A226MQ5N6J8_0402-IPC_C]  (hidden comment: CL05A226MQ5N6J8)
C35  Cap_F: 100nF  [FP-GRM033R6YA104KE14D_0201 (0603 Metric)-IPC_C]  (hidden comment: GRM033R6YA104KE14D)
C36  Cap_F: 100nF  [FP-GRM033R6YA104KE14D_0201 (0603 Metric)-IPC_C]  (hidden comment: GRM033R6YA104KE14D)
C37  Cap_F: 100nF  [FP-GRM033R6YA104KE14D_0201 (0603 Metric)-IPC_C]  (hidden comment: GRM033R6YA104KE14D)
C41  ValueDisplayed: 1pF  [0402L]  (hidden comment: GCM1555C1H1R0CA16D)
C86  Cap_F: 100nF  [FP-GRM033R6YA104KE14D_0201 (0603 Metric)-IPC_C]  (hidden comment: GRM033R6YA104KE14D)
C93  ValueDisplayed: 12pF  [0402L]  (hidden comment: CL05C120JB5NNNC)
C99  ValueDisplayed: 1.8pF  [0402L]  (hidden comment: GJM1555C1H1R8BB01D)
C104  ValueDisplayed: 1.8pF  [0402L]  (hidden comment: GJM1555C1H1R8BB01D)
C114  Cap_F: 100nF  [FP-GRM033R6YA104KE14D_0201 (0603 Metric)-IPC_C]  (hidden comment: GRM033R6YA104KE14D)
C115  Cap_F: 1µF  [FP-CL03A105MO3NRNH_0201-IPC_C]  (hidden comment: CL03A105MO3NRNH)
C116  Cap_F: 1µF  [FP-CL03A105MO3NRNH_0201-IPC_C]  (hidden comment: CL03A105MO3NRNH)
C117  Cap_F: 100nF  [FP-GRM033R6YA104KE14D_0201 (0603 Metric)-IPC_C]  (hidden comment: GRM033R6YA104KE14D)
C118  Cap_F: 100nF  [FP-GRM033R6YA104KE14D_0201 (0603 Metric)-IPC_C]  (hidden comment: GRM033R6YA104KE14D)
C119  Cap_F: 100nF  [FP-GRM033R6YA104KE14D_0201 (0603 Metric)-IPC_C]  (hidden comment: GRM033R6YA104KE14D)
J4  51441-1093  [FP-51441-1093_CONN_SMD_FFC-0]  (value not drawn)
J6  51441-1093  [FP-51441-1093_CONN_SMD_FFC-0]  (value not drawn)
J7  GRPB052MWCN-RC  [FP-GRPB052MWCN-RC_HDR10-MFG]  (value not drawn)  (parts A,B of 2)
L1  ValueDisplayed: 2.4nH  [IND_LQG15H]  (hidden comment: LQG15HS2N4S02D)
L6  ValueDisplayed: 2.4nH  [IND_LQG15H]  (hidden comment: LQG15HS2N4S02D)
L7  ValueDisplayed: 6.8uH  [0805_HV]  (hidden comment: MLZ2012N6R8LT000)
L8  BLM18HE152SN1D  [0603L]  (value not drawn)
L9  ValueDisplayed: 2nH  [IND_LQG15H]  (hidden comment: LQG15HS2N0S02D)
L10  ValueDisplayed: 2nH  [IND_LQG15H]  (hidden comment: LQG15HS2N0S02D)
LD6  APHHS1005CGCK  [APHHS1005_Green]  (value not drawn)
R17  value 220  [0201L]  (hidden comment: RC0201JR-07220RL)
R30  Res_ohm: 0  [FP-RC0201JR-070RL_0201 (0603 Metric)-MFG]  (hidden comment: RC0201JR-070RL)
R76  Res_ohm: 0  [FP-RC0201JR-070RL_0201 (0603 Metric)-IPC_C]  (hidden comment: RC0201JR-070RL)
R79  Res_ohm: 4.7k  [FP-ERJ-1GNF4701C_0201-IPC_C]  (hidden comment: ERJ-1GNF4701C)
R86  Res_ohm: 0  [FP-RC0201JR-070RL_0201 (0603 Metric)-IPC_C]  (hidden comment: RC0201JR-070RL)
R87  Res_ohm: 0  [FP-RC0201JR-070RL_0201 (0603 Metric)-IPC_C]  (hidden comment: RC0201JR-070RL)
R89  value 100k  [0201L]  (hidden comment: CRCW0201100KFKED)
R90  Res_ohm: 0  [FP-RC0201JR-070RL_0201 (0603 Metric)-IPC_C]  (hidden comment: RC0201JR-070RL)
R91  Res_ohm: 0  [FP-RC0201JR-070RL_0201 (0603 Metric)-IPC_C]  (hidden comment: RC0201JR-070RL)
R94  Res_ohm: 10k  [FP-RR0306P-103-D_0201-IPC_C]  (hidden comment: RR0306P-103-D)
R95  Res_ohm: 10k  [FP-RR0306P-103-D_0201-IPC_C]  (hidden comment: RR0306P-103-D)
R99  Res_ohm: 0  [FP-RC0201JR-070RL_0201 (0603 Metric)-IPC_C]  (hidden comment: RC0201JR-070RL)
R100  Res_ohm: 0  [FP-RC0201JR-070RL_0201 (0603 Metric)-IPC_C]  (hidden comment: RC0201JR-070RL)
R101  Res_ohm: 0  [FP-RC0201JR-070RL_0201 (0603 Metric)-IPC_C]  (hidden comment: RC0201JR-070RL)
R102  Res_ohm: 0  [FP-RC0201JR-070RL_0201 (0603 Metric)-IPC_C]  (hidden comment: RC0201JR-070RL)
R110  Res_ohm: 10k  [FP-RR0306P-103-D_0201-IPC_C]  (hidden comment: RR0306P-103-D)
R112  Res_ohm: 0  [FP-RC0201JR-070RL_0201 (0603 Metric)-IPC_C]  (hidden comment: RC0201JR-070RL)
R113  Res_ohm: 0  [FP-RC0201JR-070RL_0201 (0603 Metric)-IPC_C]  (hidden comment: RC0201JR-070RL)
R131  Res_ohm: 0  [FP-RC0201JR-070RL_0201 (0603 Metric)-IPC_C]  (hidden comment: RC0201JR-070RL)
R160  Res_ohm: 0  [FP-RC0201JR-070RL_0201 (0603 Metric)-IPC_C]  (hidden comment: RC0201JR-070RL)
R161  Res_ohm: 0  [FP-RC0201JR-070RL_0201 (0603 Metric)-IPC_C]  (hidden comment: RC0201JR-070RL)
R166  Res_ohm: 0  [FP-RC0201JR-070RL_0201 (0603 Metric)-IPC_C]  (hidden comment: RC0201JR-070RL)
R168  Res_ohm: 0  [FP-RC0201JR-070RL_0201 (0603 Metric)-IPC_C]  (hidden comment: RC0201JR-070RL)
R180  Res_ohm: 4.7k  [FP-ERJ-1GNF4701C_0201-IPC_C]  (hidden comment: ERJ-1GNF4701C)
R181  Res_ohm: 4.7k  [FP-ERJ-1GNF4701C_0201-IPC_C]  (hidden comment: ERJ-1GNF4701C)
R182  Res_ohm: 0  [FP-RC0201JR-070RL_0201 (0603 Metric)-IPC_C]  (hidden comment: RC0201JR-070RL)
R183  Res_ohm: 0  [FP-RC0201JR-070RL_0201 (0603 Metric)-IPC_C]  (hidden comment: RC0201JR-070RL)
R184  Res_ohm: 0  [FP-RC0201JR-070RL_0201 (0603 Metric)-IPC_C]  (hidden comment: RC0201JR-070RL)
R185  Res_ohm: 0  [FP-RC0201JR-070RL_0201 (0603 Metric)-IPC_C]  (hidden comment: RC0201JR-070RL)
TP16  TESTPOINT  [TP_25MIL-SMT]  (value not drawn)  (no BOM)
TP27  TESTPOINT  [TP_25MIL-SMT]  (value not drawn)  (no BOM)
TP46  TESTPOINT  [TP_25MIL-SMT]  (value not drawn)  (no BOM)
U4  TPS79330DBVR  [DBV0005A_N]
U8  CC2642R1FRGZR  [RGZ0048A]
U10  TCA6408ARSVR  [RSV0016A]
U14  TXB0104QRUTRQ1  [RUT0012A]
Y2  CX2016DB48000C0WPLA2  [FP-CX2016DB48000C0WPLA2_SMD4-MFG]  (value not drawn)
Y3  Frequency_Fixed: 32.768kHz  [FP-ABS05W-32.768KHZ-D-2-T_XTAL_SMT_1MM6_1MM0-MFG]  (hidden comment: ABS05W-32.768KHZ-D-2-T)

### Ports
ALERT (in), AR_CS1_BT (in), AR_CS1_LCD (in), AR_MSS_LOGGER (bidir), AR_RS232RX_BT (bidir), AR_RS232TX_BT (bidir), AR_SCL (bidir), AR_SDA (bidir), BT ENABLE (in), DISP (in), DISP (out), SENS_INT (in), SENS_NRST (out), SPI_CLK1 (bidir), SPI_MISO1 (bidir), SPI_MOSI1 (bidir)

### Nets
3V0: C7.1 C15.1 C16.1 C115.1 C116.1 C118.1 J4.6 J4.7 J6.6 J6.7 R79.2 R181.2 U4.5(OUT) U14.1(VCCA)
DCDC_SW: L7.1 U8.33(DCDC_SW)
GND: C5.2 C7.2 C8.2 C15.2 C16.2 C17.2 C18.2 C19.2 C20.2 C21.1 C23.2 C24.2 C25.2 C26.2 C27.2 C28.2 C29.2 C35.2 C36.2 C37.2 C41.2 C86.2 C104.2 C114.1 C115.2 C116.2 C117.2 C118.2 C119.2 J4.8 J4.9 J4.10 J4.11(MNT_1) J4.12(MNT_2) J6.8 J6.9 J6.10 J6.11(MNT_1) J6.12(MNT_2) J7.3 J7.5 LD6.2(K) R180.1 U4.2(GND) U8.49(EGP) U10.6(GND) U10.16(ADDR) U14.6(GND) Y2.2(GND) Y2.4(GND)
VCC_BA_3V3: C5.1 C117.1 C119.1 J7.1 L8.1 R89.2 R94.2 R95.2 U4.1(IN) U4.3(EN) U10.14(VCCP) U10.15(VCCI) U14.11(VCCB)
VDDR: C29.1 C35.1 C36.1 L7.2 U8.45(VDDR) U8.48(VDDR_RF)
VDDS: C25.1 C26.1 C27.1 C28.1 C86.1 L8.2 R110.2 U8.13(VDDS2) U8.22(VDDS3) U8.34(VDDS_DCDC) U8.44(VDDS)
ALERT: U10.4(P2) ; port ALERT
AR_CS1_BT: U8.30(DIO_20) ; port AR_CS1_BT
AR_CS1_LCD: R76.2 ; port AR_CS1_LCD
AR_CS1_LCD_T: J6.3 R183.1 U14.4(A3)
AR_MSS_LOGGER: R131.1 ; port AR_MSS_LOGGER
AR_RS232RX_BT: R102.1 ; port AR_RS232RX_BT
AR_RS232TX_BT: R90.1 ; port AR_RS232TX_BT
AR_SCL: R99.2 ; port AR_SCL
AR_SDA: R101.2 ; port AR_SDA
BT ENABLE: R30.1 R110.1 U8.17(DIO_11) ; port BT ENABLE
BT_RST: R91.2 U10.3(P1)
BT_UART_RX: J7.9 R90.2 U8.7(DIO_2)
BT_UART_TX: J7.10 R102.2 U8.8(DIO_3)
DIO6_GLED: R17.1 U8.11(DIO_6)
DISP: R168.2 U10.2(P0) ; port DISP
DISP_T: C114.2 J6.5 R180.2 R181.1 R182.1 U14.5(A4)
INTN: R95.1 TP46.1 U10.11(~{INT})
JTAG_TCK: J7.4 U8.25(JTAG_TCKC)
JTAG_TDI: J7.8 R113.1 U8.27(DIO_17)
JTAG_TDO: J7.6 U8.26(DIO_16)
JTAG_TMS: J7.2 U8.24(JTAG_TMSC)
MRDY: TP16.1 U8.21(DIO_15)
nRESET: C37.1 J7.7 R89.1 R91.1 U8.35(~{RESET})
RE: A1.1(Radiator_electrode)
RESETN: R94.1 U10.1(~{RESET})
RF_N: C23.1 L6.1 U8.2(RF_N)
RF_P: C22.2 L1.1 U8.1(RF_P)
SENS_INT: R100.1 ; port SENS_INT
SENS_NRST: U10.7(P4) ; port SENS_NRST
SPI_CLK1: R160.2 R161.1 ; port SPI_CLK1
SPI_CLK1_T: J6.1 R185.1 U14.2(A1)
SPI_MISO1: R87.1 R166.2 ; port SPI_MISO1
SPI_MISO1_T: J6.2 R184.1 U14.3(A2)
SPI_MOSI1: R86.1 ; port SPI_MOSI1
SRDY: R112.1 TP27.1 U8.31(DIO_21)
X32K_Q1: C19.1 U8.3(X32K_Q1) Y3.1
X32K_Q2: C20.1 U8.4(X32K_Q2) Y3.2
X48M_N: C18.1 U8.46(X24M_N) Y2.3(2_HOT)
X48M_P: C17.1 U8.47(X24M_P) Y2.1(1_HOT)
NetA1_4: A1.4(Feed_point) C99.1 C104.1
NetC8_1: C8.1 U4.4(NR)
NetC21_2: C21.2 L1.2
NetC22_1: C22.1 L6.2 L9.1
NetC24_1: C24.1 U8.23(DCOUPL)
NetC41_1: C41.1 L9.2 L10.1
NetC93_1: C93.1 C99.2
NetC93_2: C93.2 L10.2
NetJ4_1: J4.1 R185.2
NetJ4_2: J4.2 R184.2
NetJ4_3: J4.3 R183.2
NetJ4_5: J4.5 R182.2
NetLD6_1: LD6.1(A) R17.2
NetR30_2: R30.2 U10.10(P7)
NetR76_1: R76.1 U14.8(B3)
NetR79_1: R79.1 U14.12(OE)
NetR86_2: R86.2 U8.15(DIO_9)
NetR87_2: R87.2 U8.14(DIO_8)
NetR99_1: R99.1 U10.12(SCL)
NetR100_2: R100.2 U10.5(P3)
NetR101_1: R101.1 U10.13(SDA)
NetR112_2: R112.2 U10.8(P5)
NetR113_2: R113.2 U10.9(P6)
NetR131_2: R131.2 U8.29(DIO_19)
NetR160_1: R160.1 U14.10(B1)
NetR161_2: R161.2 U8.16(DIO_10)
NetR166_1: R166.1 U14.9(B2)
NetR168_1: R168.1 U14.7(B4)

Not connected (* = marked no-connect by the designer): A1 2-3(NC)* 5-6(NC)*; J4 4*; J6 4*; U8 5(DIO_0)* 6(DIO_1)* 9(DIO_4)* 10(DIO_5)* 12(DIO_7)* 18(DIO_12)* 19(DIO_13)* 20(DIO_14)* 28(DIO_18)* 32(DIO_22) 36(DIO_23) 37(DIO_24) 38(DIO_25)* 39(DIO_26)* 40(DIO_27)* 41(DIO_28)* 42(DIO_29)* 43(DIO_30)*

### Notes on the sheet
- BREAKAWAY_SECTION_3
- BLUETOOTH
- VDDR Decoupling capacitors
- Pin 45
- (near C36) Pin 48
- BT_JTAG_HEADER
- Place L7 and C29 close to pin 33
- MUX IN CONFIG
- S2.3 ON   : BT ENABLE
- S2.3 OFF : BT DISABLE
- VDDS Decoupling capacitors
- Pin 13
- Pin 22
- Pin 44
- Pin 34
- 48 MHz Crystal for BT
- Internal load capacitance considered
- GPIO EXPANDER
- LCD DISPLAY CONNECTOR-1
- LCD DISPLAY CONNECTOR-2
- LEVEL TRANSLATOR FOR DISPLAY
- ADDRESS:  0100000
- 3V3 TO 3V LDO

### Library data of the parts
A1 = CMP-0087189-1: RF ANT 2.4GHZ CHIP SOLDER SMD; Manufacturer: TDK Corporation; SizeZ_mm: 0.4mm
C5 C15 C16 C24 C115 C116 = CMP-0086446-1: as C129 on sheet PROC091F_HD_CONN_PWR_SW
C7 = CMP-0006339-4: CAP, CERM, 10 uF, 10 V, +/- 20%, X5R, 0402; Manufacturer: Samsung Electro-Mechanics; AEC Category: Q200; AEC Qualified: N; Cap_Case: 0402; Cap_F: 10µF; SizeArea_mm2: 0.5; SizeAreaWB_mm2: 3; SizeX_mm: 1; SizeZ_mm: 0.6; TaMax_C: 85°C; TaMin_C: -55°C; U/M: EA; Value1: Unknown; Value2: 10V
C8 = CMP-0086445-1: as C125 on sheet PROC091F_RST_GPIOs_I2C
C17 C18 = CMP-0086441-1: Cap Ceramic 8pF 50V C0G 0.1pF SMD 0201 125°C Paper T/R; Manufacturer: Murata; AEC Qualified: No; SizeZ_mm: 0.33mm; Symbol Name: SYM-GRM0335C1H8R0BA01D; TempCo: 30ppm/°C
C19 C20 = CMP-0087190-1: as C38 on sheet PROC091F_RST_GPIOs_I2C
C21 C93 = CMP-0006345-2: CAP, CERM, 12 pF, 50 V, +/- 5%, C0G/NP0, 0402; Manufacturer: Samsung Electro-Mechanics; TaMin_C: -55°C; Polarized: N; SizeAreaWB_mm2: 3; Value1: Unknown; U/M: EA; Value: 12pF; TaMax_C: 125°C; SizeZ_mm: 0.6; SizeX_mm: 1; SizeY_mm: 0.5; Cap_Case: 0402; Value2: 50V; AEC Category: Q200
C22 C23 C41 = CMP-0085178-1: CAP, CERM, 1 pF, 50 V,+/- 25%, C0G/NP0, AEC-Q200 Grade 1, 0402; Manufacturer: MuRata; SizeX_mm: 1; Polarized: N; AEC Qualified: Y; AEC Category: Q200; VDC_V: 50V; Cap_Case: 0402; TaMax_C: 125°C; TaMin_C: -55°C; U/M: EA; Value: 1pF; SizeY_mm: 0.5; SizeAreaWB_mm2: 3; SizeZ_mm: 0.6
C25-C27 C35-C37 C86 C114 C117-C119 = CMP-0086440-1: as C127 on sheet PROC091F_HD_CONN_PWR_SW
C28 C29 = CMP-0089043-3: CAP CER 22UF 6.3V X5R 0402; Manufacturer: Samsung Electro-Mechanics; AEC Qualified: No; SizeZ_mm: 0.55mm; TempCo: 15%; Tolerance_%: 20%
C99 C104 = CMP-0086306-1: CAP, CERM, 1.8 pF, 50 V,+/- 6%, C0G/NP0, 0402; Manufacturer: MuRata; VDC_V: 50V; SizeZ_mm: 0.6; SizeAreaWB_mm2: 3; SizeArea_mm2: 0.5; Polarized: N; TaMax_C: 125°C; Cap_Case: 0402; SizeX_mm: 1; Value: 1.8pF; U/M: EA; TaMin_C: -55°C; AEC Category: Q200
J4 J6 = CMP-0086453-1: Easy-On™ Type FFC/FPC Connector, Right-Angle, Surface Mount, ZIF, Bottom Contact Style, 1.10mm Mated Height, 10 Circuits; Manufacturer: Molex
J7 = CMP-0087786-1: CONN HEADER R/A 10POS 1.27MM; Manufacturer: Sullins; Row_Count: 2; Current_A: 1A; ContactFinish: Gold
L1 L6 = CMP-0058626-1: Inductor, Multilayer, Air Core, 2.4 nH, 0.3 A, 0.15 ohm, SMD; Manufacturer: MuRata; Isat: 0.3A @ % inductance drop; Irms: 0.3A @ C rise; Green_Lifecycle: Active; SizeAreaWB_mm2: 3; DCR_ohm: 0.15; Green_REACh: Passed; Value: 2.4nH; Imax_A: 300mA; SizeZ_mm: 0.55; SizeX_mm: 1; SizeY_mm: 0.5; Value2: 0.3A; AEC Category: Q200
L7 = CMP-0062727-1: Inductor, Multilayer, Ferrite, 6.8 uH, 0.11 A, 0.25 ohm, SMD; Manufacturer: TDK; Isat: 0.11A @ 50% inductance drop; Irms: 0.55A @ 20C rise; Green_Lifecycle: Active; SizeAreaWB_mm2: 6.75; DCR_ohm: 0.25; Green_REACh: Passed; Value: 6.8uH; Imax_A: 110mA; SizeZ_mm: 1.45; SizeX_mm: 2; SizeY_mm: 1.25; Value2: 0.11A; SizeArea_mm2: 2.5; Ind_H: 6.8µH; AEC Category: Q200
L8 = CMP-0003349-2: Ferrite Bead, 1500 ohm @ 100 MHz, 0.5 A, 0603; Manufacturer: MuRata; Ztyp@1GHz_Ohm: 1.5k; SizeAreaWB_mm2: 4.68; DCR_ohm: 0.5; Value1: 0.5 ohm; Imax_A: 500mA; SizeZ_mm: 1; SizeX_mm: 1.6; SizeY_mm: 0.8; Value2: 0.5A; SizeArea_mm2: 1.28
L9 L10 = CMP-0058624-1: Inductor, Multilayer, Air Core, 2 nH, 0.3 A, 0.1 ohm, SMD; Manufacturer: MuRata; Isat: 0.3A @ % inductance drop; Irms: 0.3A @ C rise; Green_Lifecycle: Active; SizeAreaWB_mm2: 3; DCR_ohm: 0.1; Green_REACh: Passed; Value1: 0.1 ohm; Value: 2nH; Imax_A: 300mA; SizeZ_mm: 0.55; SizeX_mm: 1; SizeY_mm: 0.5; Value2: 0.3A; AEC Category: Q200
LD6 = CMP-0067682-2: as LD2 on sheet PROC091F_RST_GPIOs_I2C
R17 = CMP-0027072-1: as R13 on sheet PROC091F_RST_GPIOs_I2C
R30 R76 R86 R87 R90 R91 R99-R102 R112 R113 R131 R160 R161 R166 R168 R182-R185 = CMP-0086442-2: as R12 on sheet PROC091F_HD_CONN_PWR_SW
R79 R180 R181 = CMP-0087184-1: RESISTOR, 0201, 0.05W, 1%, 4K7; Manufacturer: Panasonic Electronic Components; AEC Grade: Grade 1; AEC Qualified: Yes; Power_W: 50mW; SizeZ_mm: 0.26mm; Symbol Name: SYM-ERJ-1GNF4701C; TempCo: 200ppm/°C; VDC_V: 25V
R89 = CMP-0027261-3: as R29 on sheet PROC091F_HD_CONN_PWR_SW
R94 R95 R110 = CMP-0088002-1: as R20 on sheet PROC091F_HD_CONN_PWR_SW
TP16 TP27 TP46 = CMP-0078143-3: TEST POINT.  No entry in BOM.
U4 = CMP-0035419-1: Single Output High PSRR LDO, 200 mA, Fixed 3 V Output, 2.7 to 5.5 V Input, 5-pin SOT-23 (DBV), -40 to 85 degC, Green (RoHS & no Sb/Br); Manufacturer: Texas Instruments; Accuracy(%): 2; Fixed Output Options(V): 3; Iout(Max)(A): 0.2; Rating: Catalog; SubFamily: Single Channel LDO; Vdo(Typ)(mV): 112; Vin(Max)(V): 5.5; Vin(Min)(V): 2.7
U8 = CMP-0083675-2: SimpleLink(TM) Bluetooth(R) 5 low energy Wireless MCU, RGZ0048A (VQFN-48); Alternate Manufacturer: Texas Instruments; Alternate PartNumber: CC2642R1FRGZT; SizeZ_mm: 1; AEC Category: Q200; SizeY_mm: 7; Rating: #N/A; SizeAreaWB_mm2: 81; AEC Qualified: N; CompType: IC; SizeArea_mm2: 49
U10 = CMP-0043349-1: Low-Voltage 8-Bit I2C and SMBus I/O Expander, 1.65 to 5.5 V, -40 to 85 degC, 16-pin UQFN (RSV), Green (RoHS & no Sb/Br); Manufacturer: Texas Instruments; # of I/Os: 8; 5V Tolerant I/O: Yes; fSCLK(Max)(MHz): 400; I2C Address: 0100 00x; SubFamily: I2C IO Expander; VCC(Max)(V): 5.5; VCC(Min)(V): 1.65
U14 = CMP-0860038-1: Automotive 4-Bit Bidirectional Voltage-Level Translator with Auto Direction Sensing and +/-15kV ESD, RUT0012A (UQFN-12); Alternate Manufacturer: Texas Instruments; AEC Category: Q200; AEC Qualified: Y; CompType: IC; SizeArea_mm2: 3.4; SizeAreaWB_mm2: 8.1; SizeX_mm: 1.7; SizeY_mm: 2; SizeZ_mm: 0.55
Y2 = CMP-0088076-1: 48MHz ±20ppm Crystal 7pF 50 Ohms 4-SMD, No Lead; Manufacturer: Kyocera; SizeZ_mm: 0.45mm
Y3 = CMP-0088006-1: as Y4 on sheet PROC091F_RST_GPIOs_I2C

## Sheet PROC091F_ANALOG_MUX.SchDoc: BREAKAWAY_SECTION4
size 431 x 279 mm; Date: Not shown in title block; ApprovedBy: Not shown in title block; CheckedBy: Not shown in title block; Author: Not shown in title block; CompanyName: Not shown in title block; DrawnBy: Antony/Bala; Engineer: Not shown in title block; Organization: Not shown in title block; Address1: Not shown in title block; Address2: Not shown in title block; Address3: Not shown in title block; Address4: Not shown in title block; DocumentNumber: 10; Revision: Use project parameter SCH_Rev; SheetNumber: 10; SheetTotal: 12; PageSetup: Record=PageOptions¦CenterHorizontal=True¦CenterVertical=True¦PrintScale=1.00¦XCorrection=1.00¦YCorrection=1.00¦PrintKind=0¦BorderSize=5000000¦LeftOffset=0¦BottomOffset=0¦Orientation=2¦PaperLength=1000¦PaperWidth=1000¦Scale=100¦PaperSource=15¦PrintQuality=600¦MediaType=1¦DitherType=10¦PaperKind=Letter¦PrintScaleMode=1

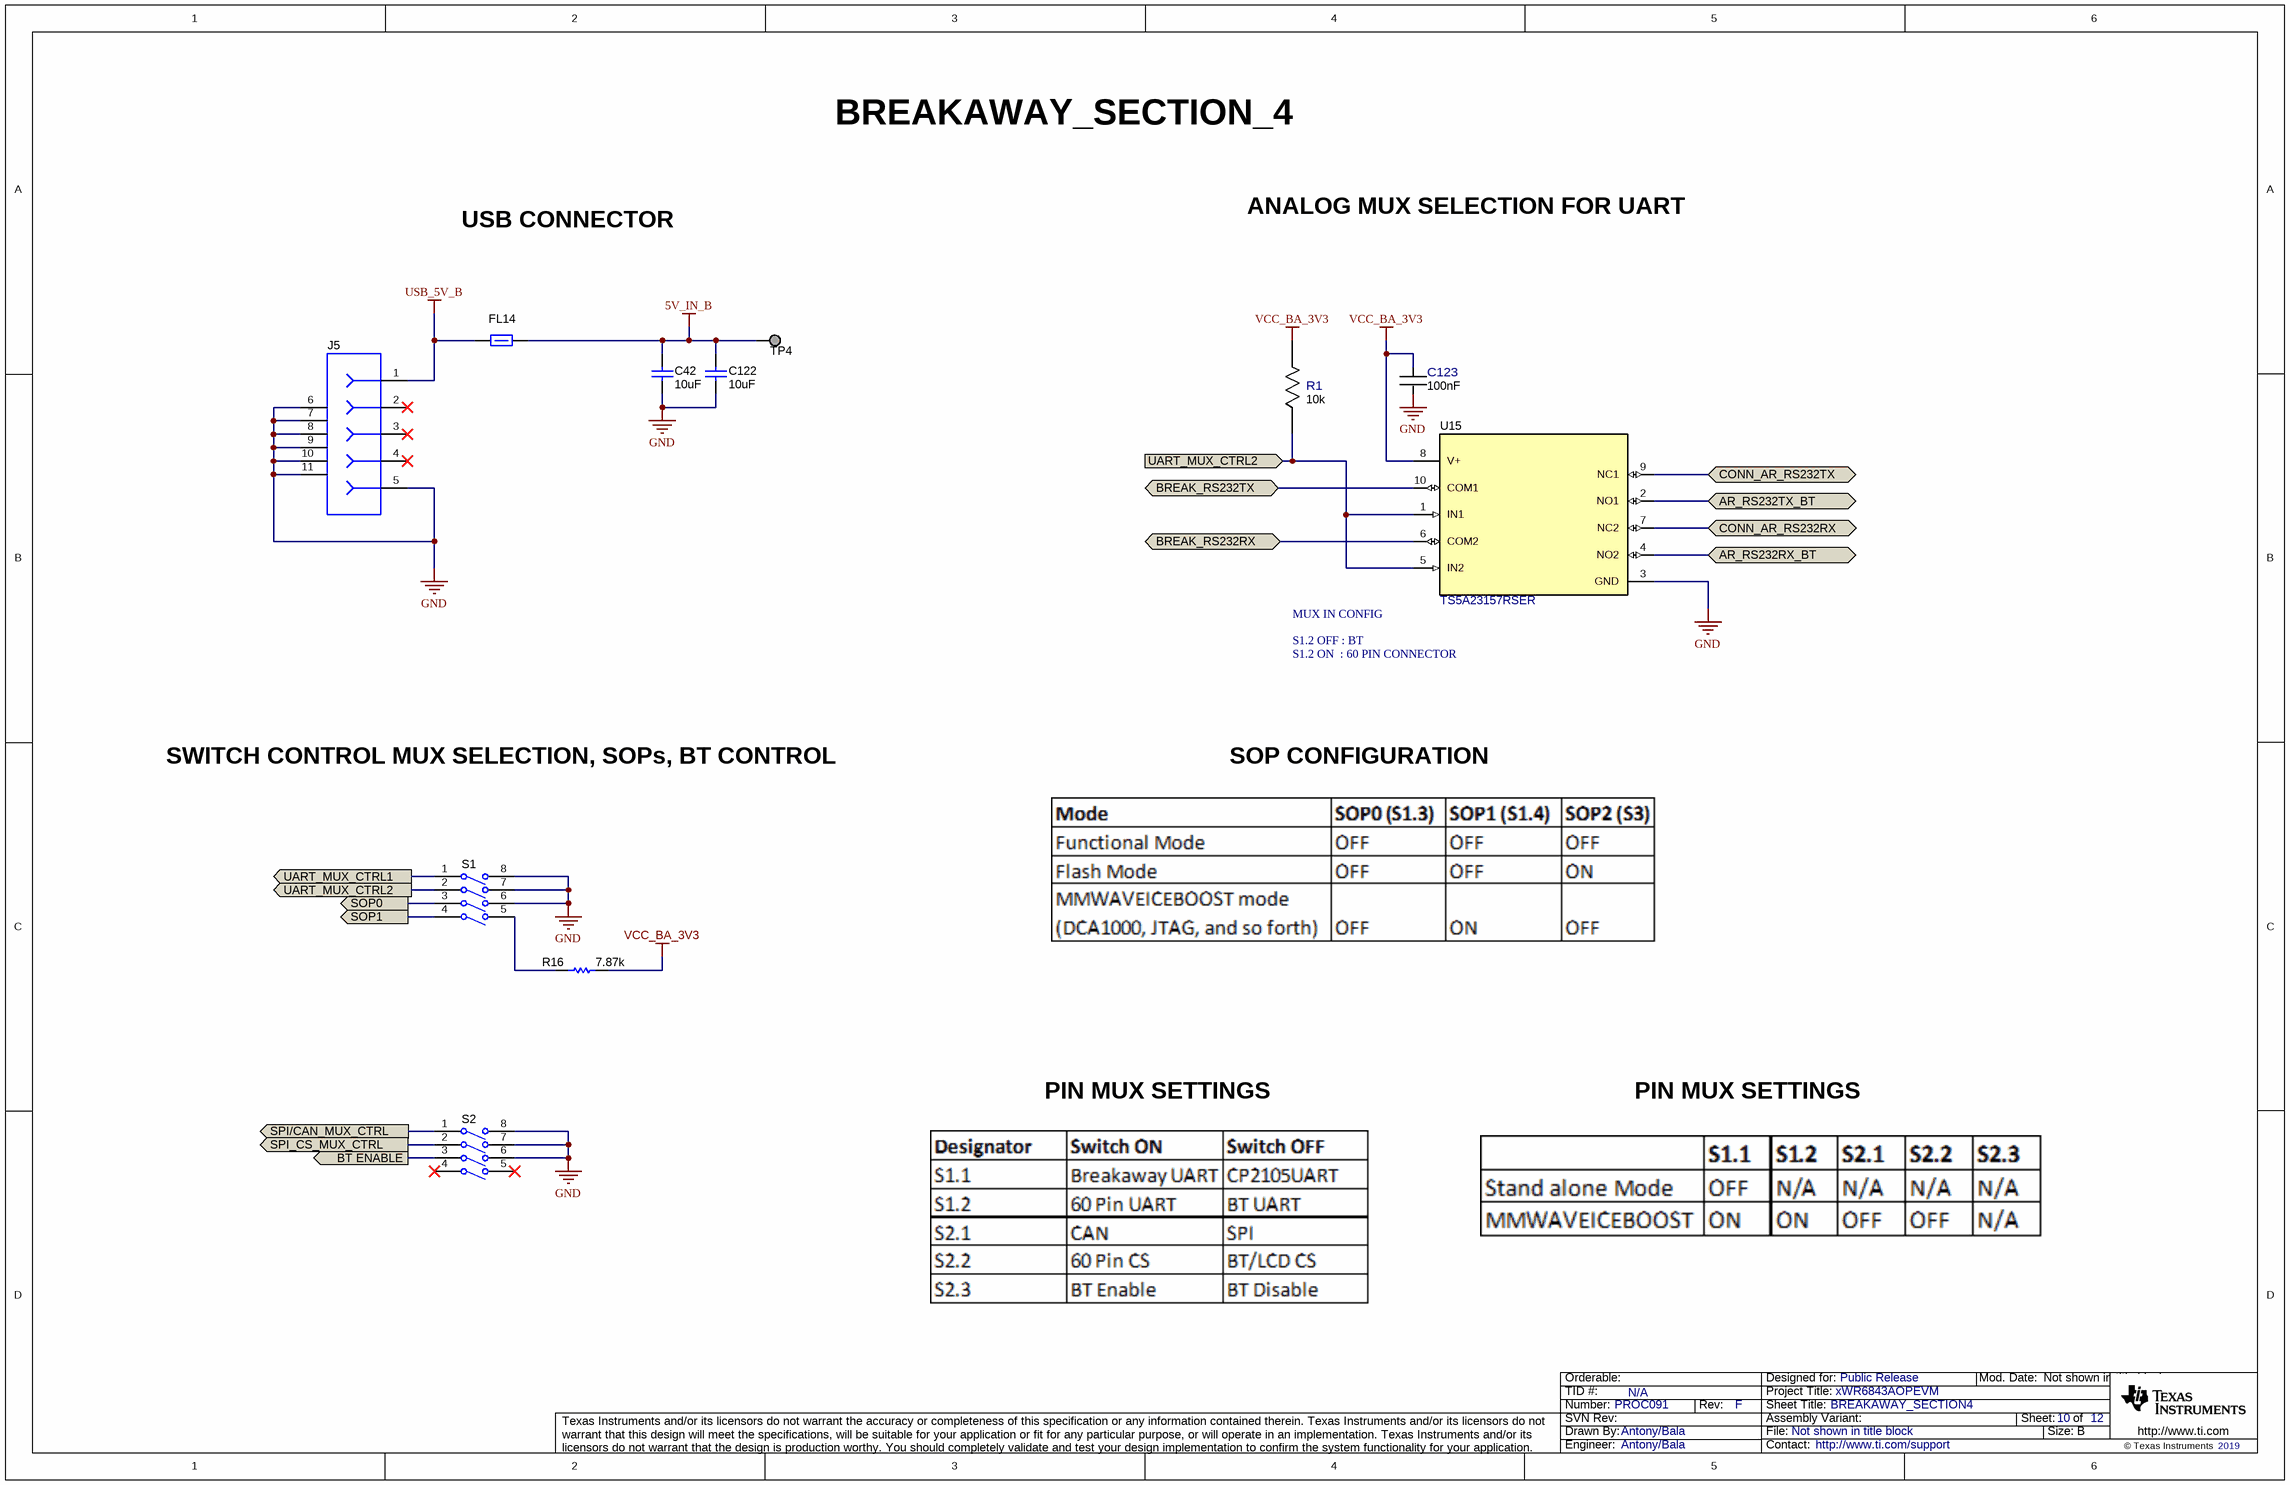
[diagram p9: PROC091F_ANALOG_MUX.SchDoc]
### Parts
C42  value 10uF  [0402_070]  (hidden comment: CL05A106MP5NUNC)
C122  value 10uF  [0402_070]  (hidden comment: CL05A106MP5NUNC)
C123  Cap_F: 100nF  [FP-GRM033R6YA104KE14D_0201 (0603 Metric)-IPC_C]  (hidden comment: GRM033R6YA104KE14D)
FL14  BLM15PD300SZ1D  [0402L]  (value not drawn)
J5  105017-0001  [CONN_105017-0001]  (value not drawn)
R1  Res_ohm: 10k  [FP-RR0306P-103-D_0201-IPC_C]  (hidden comment: RR0306P-103-D)
R16  value 7.87k  [0201L]  (hidden comment: RC0201FR-077K87L)
S1  218-4LPST  [SW_218-4LPST]  (value not drawn)
S2  218-4LPST  [SW_218-4LPST]  (value not drawn)
TP4  TESTPOINT  [TP_25MIL-SMT]  (value not drawn)  (no BOM)
U15  TS5A23157RSER  [RSE0010A]

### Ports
AR_RS232RX_BT (bidir), AR_RS232TX_BT (bidir), BREAK_RS232RX (bidir), BREAK_RS232TX (bidir), BT ENABLE (out), CONN_AR_RS232RX (bidir), CONN_AR_RS232TX (bidir), SOP0 (out), SOP1 (out), SPI/CAN_MUX_CTRL (out), SPI_CS_MUX_CTRL (out), UART_MUX_CTRL1 (out), UART_MUX_CTRL2 (in), UART_MUX_CTRL2 (out)

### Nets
5V_IN_B: C42.2 C122.1 FL14.2 TP4.1
GND: C42.1 C122.2 C123.2 J5.5 J5.6 J5.7 J5.8 J5.9 J5.10 J5.11 S1.6(B3) S1.7(B2) S1.8(B1) S2.6(B3) S2.7(B2) S2.8(B1) U15.3(GND)
USB_5V_B: FL14.1 J5.1
VCC_BA_3V3: C123.1 R1.2 R16.1 U15.8(V+)
AR_RS232RX_BT: U15.4(NO2) ; port AR_RS232RX_BT
AR_RS232TX_BT: U15.2(NO1) ; port AR_RS232TX_BT
BREAK_RS232RX: U15.6(COM2) ; port BREAK_RS232RX
BREAK_RS232TX: U15.10(COM1) ; port BREAK_RS232TX
BT ENABLE: S2.3(A3) ; port BT ENABLE
CONN_AR_RS232RX: U15.7(NC2) ; port CONN_AR_RS232RX
CONN_AR_RS232TX: U15.9(NC1) ; port CONN_AR_RS232TX
SOP0: S1.3(A3) ; port SOP0
SOP1: S1.4(A4) ; port SOP1
SPI/CAN_MUX_CTRL: S2.1(A1) ; port SPI/CAN_MUX_CTRL
SPI_CS_MUX_CTRL: S2.2(A2) ; port SPI_CS_MUX_CTRL
UART_MUX_CTRL1: S1.1(A1) ; port UART_MUX_CTRL1
UART_MUX_CTRL2: R1.1 S1.2(A2) U15.1(IN1) U15.5(IN2) ; port UART_MUX_CTRL2
NetR16_2: R16.2 S1.5(B4)

Not connected (* = marked no-connect by the designer): J5 2* 3* 4*; S2 4(A4)* 5(B4)*

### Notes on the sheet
- BREAKAWAY_SECTION_4
- USB CONNECTOR
- ANALOG MUX SELECTION FOR UART
- MUX IN CONFIG
- S1.2 ON  : 60 PIN CONNECTOR
- S1.2 OFF : BT
- SWITCH CONTROL MUX SELECTION, SOPs, BT CONTROL
- SOP CONFIGURATION
- PIN MUX SETTINGS

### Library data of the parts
C42 C122 = CMP-0006339-4: as C7 on sheet PROC091F_BT_DISPLAY
C123 = CMP-0086440-1: as C127 on sheet PROC091F_HD_CONN_PWR_SW
FL14 = CMP-0078934-1: as FL11 on sheet PROC091F_HD_CONN_PWR_SW
J5 = CMP-0055293-1: Connector, Receptacle, Micro-USB Type B, R/A, Bottom Mount SMT; Manufacturer: Molex; CNHeader: FALSE; CompType: USB; CT: TRUE; Gender: Female; Green_Lifecycle: Active; Green_REACh: Passed
R1 = CMP-0088002-1: as R20 on sheet PROC091F_HD_CONN_PWR_SW
R16 = CMP-0027880-1: RES, 7.87 k, 1%, 0.05 W, 0201; Manufacturer: Yageo America; AEC Category: Q200; AEC Qualified: N; EIA_Code: E96; Power_W: 50mW; SizeArea_mm2: 0.18; SizeX_mm: 0.6; SizeY_mm: 0.3; SizeZ_mm: 0.26; TempCo: 200 ppm/C; U/M: EA; Value2: 0.05W; Value_Code: 7k87; VDC_V: 25V
S1 S2 = CMP-0002128-2: Switch, Slide, SPST 4 poles, SMT; Manufacturer: CTS Electrocomponents; CurrentRating_mA: 25A; PositionCount: 4; VDC_V: 24V; SwitchFunction: Off-On
TP4 = CMP-0078143-3: TEST POINT.  No entry in BOM.
U15 = CMP-0074545-1: Dual 10-ohm SPDT Analog Switch, RSE0010A (UQFN-10); Alternate Manufacturer: Texas Instruments; CompType: IC; SizeArea_mm2: 3.0; SizeAreaWB_mm2: 7.5; SizeX_mm: 1.5; SizeY_mm: 2.0; SizeZ_mm: 0.6; U/M: EA

## Sheet PROC091F_CAN_INTERFACE.SchDoc: BREAKAWAY_SECTION5
size 431 x 279 mm; Date: Not shown in title block; ApprovedBy: Not shown in title block; CheckedBy: Not shown in title block; Author: Not shown in title block; CompanyName: Not shown in title block; DrawnBy: Antony/Bala; Engineer: Not shown in title block; Organization: Not shown in title block; Address1: Not shown in title block; Address2: Not shown in title block; Address3: Not shown in title block; Address4: Not shown in title block; DocumentNumber: 11; Revision: Use project parameter SCH_Rev; SheetNumber: 11; SheetTotal: 12; PageSetup: Record=PageOptions¦CenterHorizontal=True¦CenterVertical=True¦PrintScale=1.00¦XCorrection=1.00¦YCorrection=1.00¦PrintKind=0¦BorderSize=5000000¦LeftOffset=0¦BottomOffset=0¦Orientation=2¦PaperLength=1000¦PaperWidth=1000¦Scale=100¦PaperSource=15¦PrintQuality=600¦MediaType=1¦DitherType=10¦PaperKind=Letter¦PrintScaleMode=1

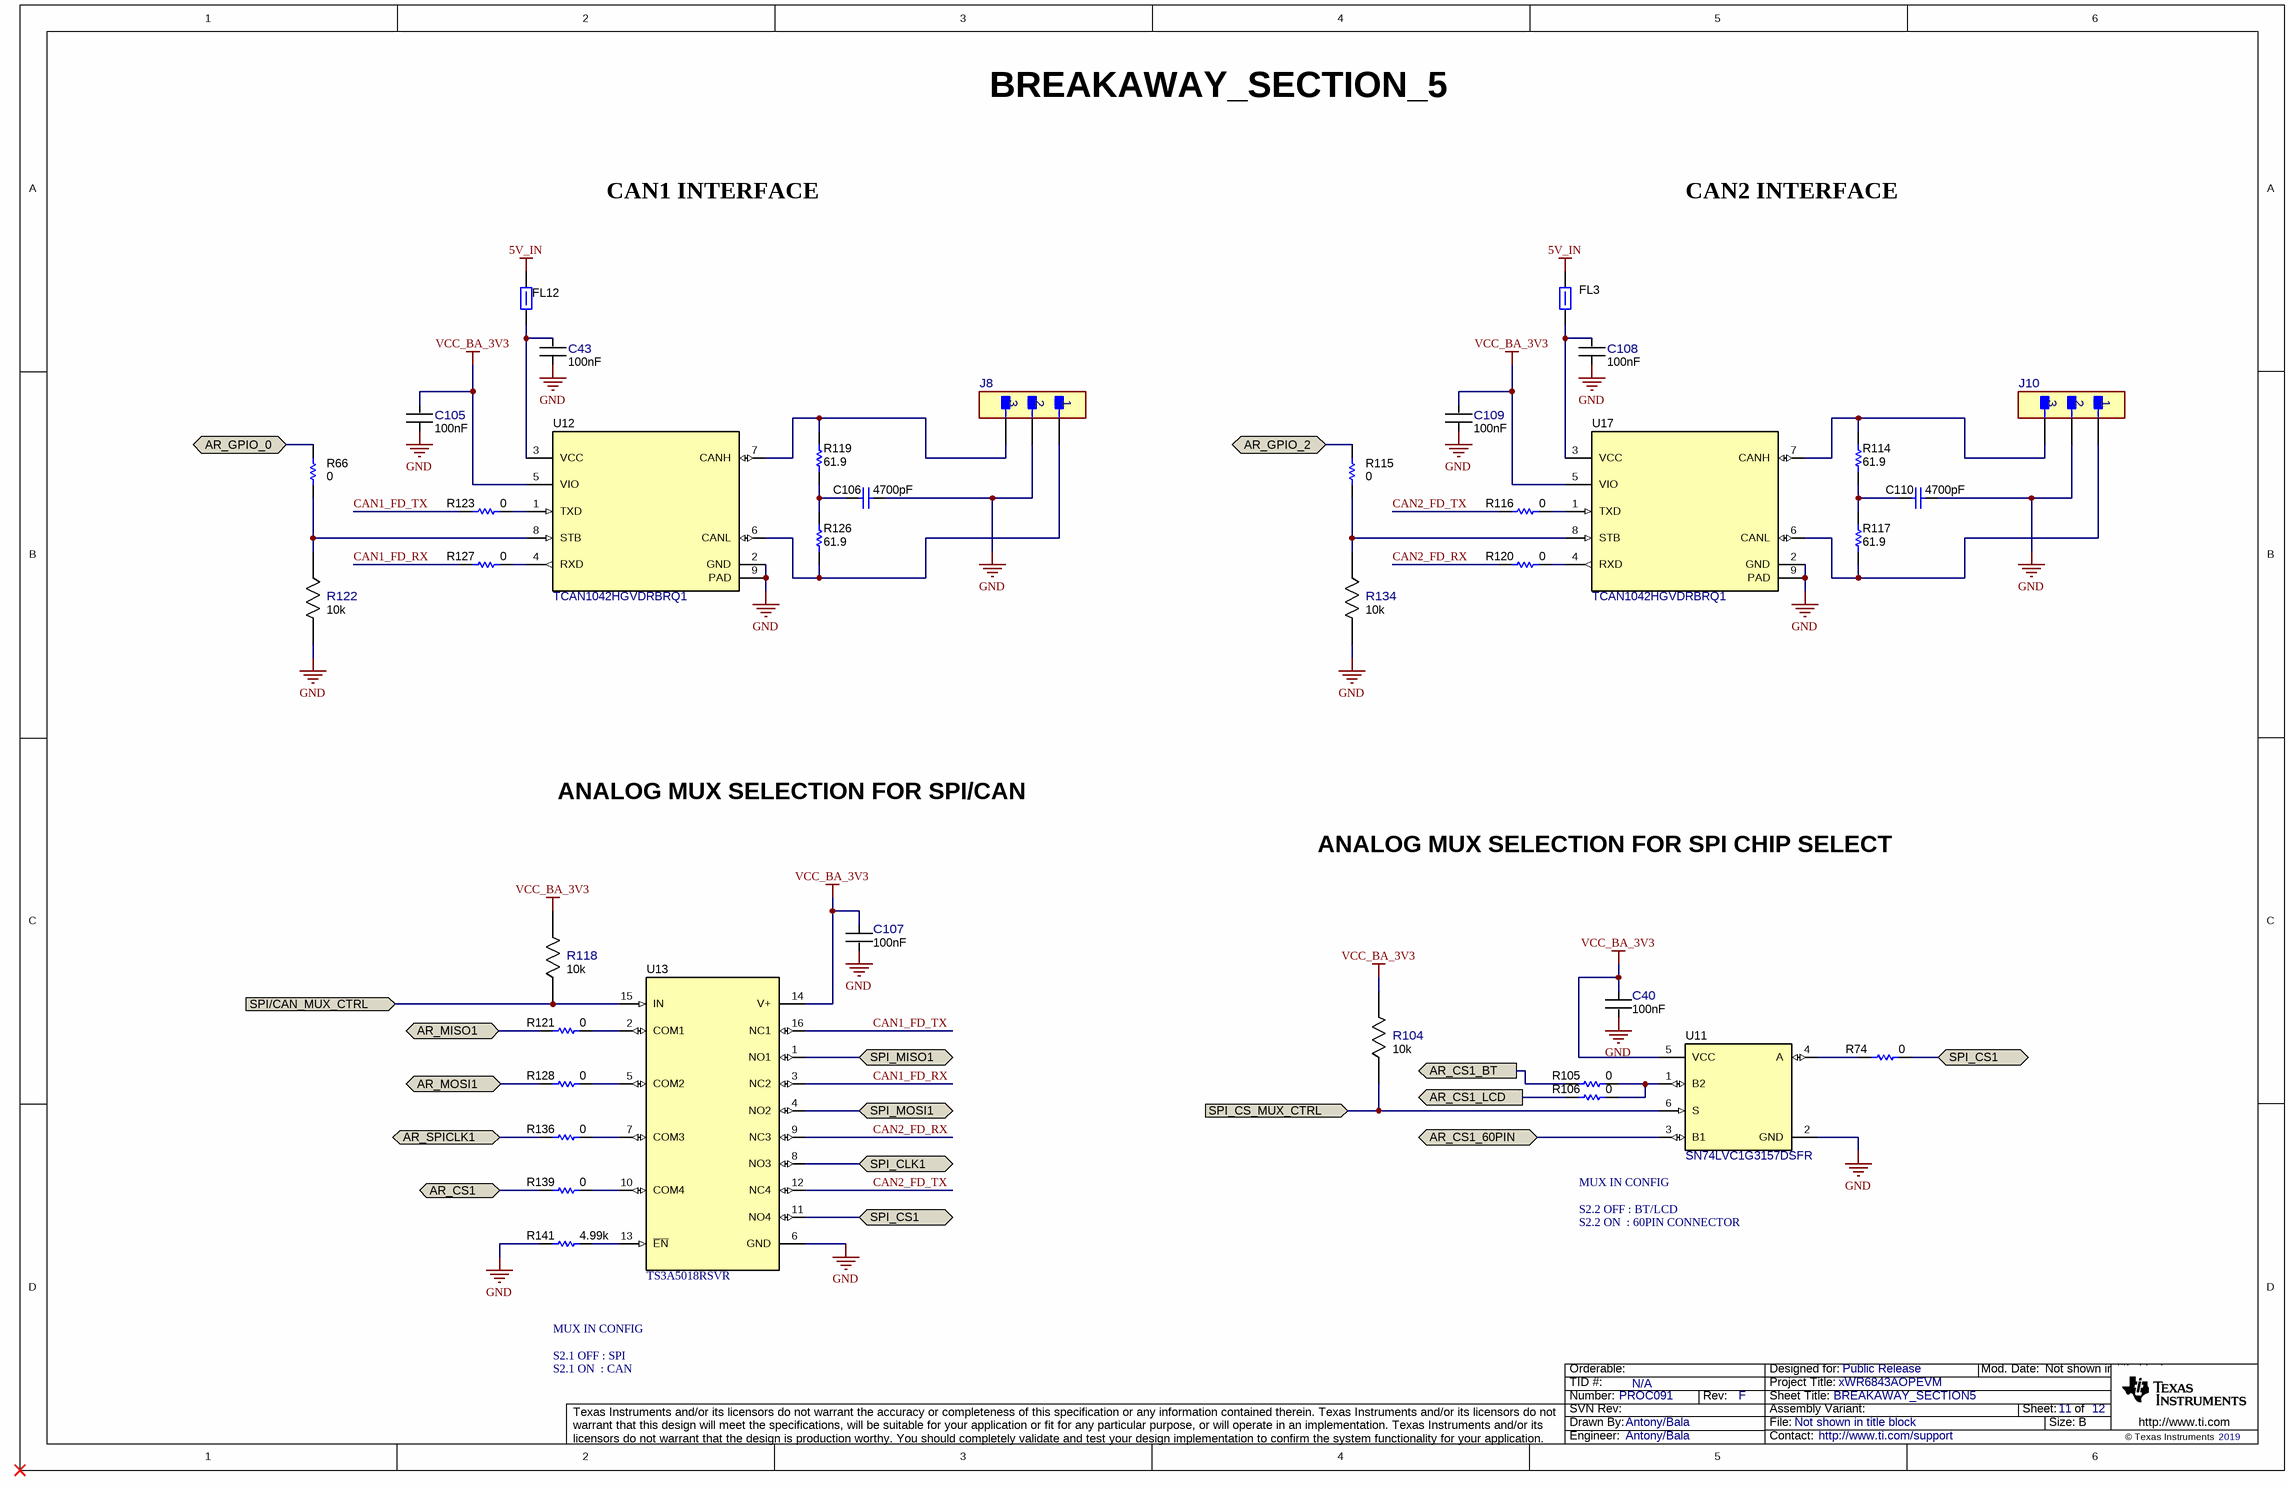
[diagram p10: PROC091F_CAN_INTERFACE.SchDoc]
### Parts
C40  Cap_F: 100nF  [FP-GRM033R6YA104KE14D_0201 (0603 Metric)-IPC_C]  (hidden comment: GRM033R6YA104KE14D)
C43  Cap_F: 100nF  [FP-GRM033R6YA104KE14D_0201 (0603 Metric)-IPC_C]  (hidden comment: GRM033R6YA104KE14D)
C105  Cap_F: 100nF  [FP-GRM033R6YA104KE14D_0201 (0603 Metric)-IPC_C]  (hidden comment: GRM033R6YA104KE14D)
C106  ValueDisplayed: 4700pF  [0402L]  (hidden comment: GRM155R71H472KA01D)
C107  Cap_F: 100nF  [FP-GRM033R6YA104KE14D_0201 (0603 Metric)-IPC_C]  (hidden comment: GRM033R6YA104KE14D)
C108  Cap_F: 100nF  [FP-GRM033R6YA104KE14D_0201 (0603 Metric)-IPC_C]  (hidden comment: GRM033R6YA104KE14D)
C109  Cap_F: 100nF  [FP-GRM033R6YA104KE14D_0201 (0603 Metric)-IPC_C]  (hidden comment: GRM033R6YA104KE14D)
C110  ValueDisplayed: 4700pF  [0402L]  (hidden comment: GRM155R71H472KA01D)
FL3  BLM15PD300SZ1D  [0402L]  (value not drawn)
FL12  BLM15PD300SZ1D  [0402L]  (value not drawn)
J8  M50-3930342  [FP-M50-3930342_HDR3-MFG]  (value not drawn)
J10  M50-3930342  [FP-M50-3930342_HDR3-MFG]  (value not drawn)
R66  Res_ohm: 0  [FP-RC0201JR-070RL_0201 (0603 Metric)-IPC_C]  (hidden comment: RC0201JR-070RL)
R74  Res_ohm: 0  [FP-RC0201JR-070RL_0201 (0603 Metric)-IPC_C]  (hidden comment: RC0201JR-070RL)
R104  Res_ohm: 10k  [FP-RR0306P-103-D_0201-IPC_C]  (hidden comment: RR0306P-103-D)
R105  Res_ohm: 0  [FP-RC0201JR-070RL_0201 (0603 Metric)-IPC_C]  (hidden comment: RC0201JR-070RL)
R106  Res_ohm: 0  [FP-RC0201JR-070RL_0201 (0603 Metric)-IPC_C]  (hidden comment: RC0201JR-070RL)
R114  ValueDisplayed: 61.9  [0402L]  (hidden comment: CRCW040261R9FKED)
R115  Res_ohm: 0  [FP-RC0201JR-070RL_0201 (0603 Metric)-IPC_C]  (hidden comment: RC0201JR-070RL)
R116  Res_ohm: 0  [FP-RC0201JR-070RL_0201 (0603 Metric)-IPC_C]  (hidden comment: RC0201JR-070RL)
R117  ValueDisplayed: 61.9  [0402L]  (hidden comment: CRCW040261R9FKED)
R118  Res_ohm: 10k  [FP-RR0306P-103-D_0201-IPC_C]  (hidden comment: RR0306P-103-D)
R119  ValueDisplayed: 61.9  [0402L]  (hidden comment: CRCW040261R9FKED)
R120  Res_ohm: 0  [FP-RC0201JR-070RL_0201 (0603 Metric)-IPC_C]  (hidden comment: RC0201JR-070RL)
R121  Res_ohm: 0  [FP-RC0201JR-070RL_0201 (0603 Metric)-IPC_C]  (hidden comment: RC0201JR-070RL)
R122  Res_ohm: 10k  [FP-RR0306P-103-D_0201-IPC_C]  (hidden comment: RR0306P-103-D)
R123  Res_ohm: 0  [FP-RC0201JR-070RL_0201 (0603 Metric)-IPC_C]  (hidden comment: RC0201JR-070RL)
R126  ValueDisplayed: 61.9  [0402L]  (hidden comment: CRCW040261R9FKED)
R127  Res_ohm: 0  [FP-RC0201JR-070RL_0201 (0603 Metric)-IPC_C]  (hidden comment: RC0201JR-070RL)
R128  Res_ohm: 0  [FP-RC0201JR-070RL_0201 (0603 Metric)-IPC_C]  (hidden comment: RC0201JR-070RL)
R134  Res_ohm: 10k  [FP-RR0306P-103-D_0201-IPC_C]  (hidden comment: RR0306P-103-D)
R136  Res_ohm: 0  [FP-RC0201JR-070RL_0201 (0603 Metric)-IPC_C]  (hidden comment: RC0201JR-070RL)
R139  Res_ohm: 0  [FP-RC0201JR-070RL_0201 (0603 Metric)-IPC_C]  (hidden comment: RC0201JR-070RL)
R141  value 4.99k  [0201L]  (hidden comment: RC0201FR-074K99L)
U11  SN74LVC1G3157DSFR  [DSF0006A]
U12  TCAN1042HGVDRBRQ1  [DRB0008F]
U13  TS3A5018RSVR  [RSV0016A]
U17  TCAN1042HGVDRBRQ1  [DRB0008F]

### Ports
AR_CS1 (bidir), AR_CS1_60PIN (bidir), AR_CS1_BT (out), AR_CS1_LCD (out), AR_GPIO_0 (bidir), AR_GPIO_2 (bidir), AR_MISO1 (bidir), AR_MOSI1 (bidir), AR_SPICLK1 (bidir), SPI/CAN_MUX_CTRL (in), SPI_CLK1 (bidir), SPI_CS1 (bidir), SPI_CS_MUX_CTRL (in), SPI_MISO1 (bidir), SPI_MOSI1 (bidir)

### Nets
5V_IN: FL3.2 FL12.2
GND: C40.2 C43.1 C105.1 C106.1 C107.2 C108.1 C109.1 C110.1 J8.2 J10.2 R122.2 R134.2 R141.2 U11.2(GND) U12.2(GND) U12.9(PAD) U13.6(GND) U17.2(GND) U17.9(PAD)
VCC_BA_3V3: C40.1 C105.2 C107.1 C109.2 R104.2 R118.2 U11.5(VCC) U12.5(VIO) U13.14(V+) U17.5(VIO)
AR_CS1: R139.2 ; port AR_CS1
AR_CS1_60PIN: U11.3(B1) ; port AR_CS1_60PIN
AR_CS1_BT: R105.2 ; port AR_CS1_BT
AR_CS1_LCD: R106.2 ; port AR_CS1_LCD
AR_GPIO_0: R66.1 ; port AR_GPIO_0
AR_GPIO_2: R115.1 ; port AR_GPIO_2
AR_MISO1: R121.2 ; port AR_MISO1
AR_MOSI1: R128.2 ; port AR_MOSI1
AR_SPICLK1: R136.2 ; port AR_SPICLK1
CAN1_FD_RX: R127.2 U13.3(NC2)
CAN1_FD_TX: R123.2 U13.16(NC1)
CAN2_FD_RX: R120.2 U13.9(NC3)
CAN2_FD_TX: R116.2 U13.12(NC4)
SPI/CAN_MUX_CTRL: R118.1 U13.15(IN) ; port SPI/CAN_MUX_CTRL
SPI_CLK1: U13.8(NO3) ; port SPI_CLK1
SPI_CS1: R74.1 U13.11(NO4) ; port SPI_CS1
SPI_CS_MUX_CTRL: R104.1 U11.6(S) ; port SPI_CS_MUX_CTRL
SPI_MISO1: U13.1(NO1) ; port SPI_MISO1
SPI_MOSI1: U13.4(NO2) ; port SPI_MOSI1
NetC43_2: C43.2 FL12.1 U12.3(VCC)
NetC106_2: C106.2 R119.1 R126.2
NetC108_2: C108.2 FL3.1 U17.3(VCC)
NetC110_2: C110.2 R114.1 R117.2
NetJ8_1: J8.1 R126.1 U12.6(CANL)
NetJ8_3: J8.3 R119.2 U12.7(CANH)
NetJ10_1: J10.1 R117.1 U17.6(CANL)
NetJ10_3: J10.3 R114.2 U17.7(CANH)
NetR66_2: R66.2 R122.1 U12.8(STB)
NetR74_2: R74.2 U11.4(A)
NetR105_1: R105.1 R106.1 U11.1(B2)
NetR115_2: R115.2 R134.1 U17.8(STB)
NetR116_1: R116.1 U17.1(TXD)
NetR120_1: R120.1 U17.4(RXD)
NetR121_1: R121.1 U13.2(COM1)
NetR123_1: R123.1 U12.1(TXD)
NetR127_1: R127.1 U12.4(RXD)
NetR128_1: R128.1 U13.5(COM2)
NetR136_1: R136.1 U13.7(COM3)
NetR139_1: R139.1 U13.10(COM4)
NetR141_1: R141.1 U13.13(~{EN})

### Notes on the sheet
- BREAKAWAY_SECTION_5
- CAN1 INTERFACE
- CAN2 INTERFACE
- ANALOG MUX SELECTION FOR SPI/CAN
- ANALOG MUX SELECTION FOR SPI CHIP SELECT
- (near U11) MUX IN CONFIG
- S2.2 ON  : 60PIN CONNECTOR
- S2.2 OFF : BT/LCD
- MUX IN CONFIG
- S2.1 OFF : SPI
- S2.1 ON  : CAN

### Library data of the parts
C40 C43 C105 C107-C109 = CMP-0086440-1: as C127 on sheet PROC091F_HD_CONN_PWR_SW
C106 C110 = CMP-0006692-2: CAP, CERM, 4700 pF, 50 V, +/- 10%, X7R, 0402; Manufacturer: MuRata; TaMin_C: -55°C; Polarized: N; SizeAreaWB_mm2: 3; Value1: Unknown; U/M: EA; Value: 4700pF; TaMax_C: 125°C; SizeZ_mm: 0.6; SizeX_mm: 1; SizeY_mm: 0.5; Cap_Case: 0402; Value2: 50V; Cap_F: 4.7nF; AEC Category: Q200
FL3 FL12 = CMP-0078934-1: as FL11 on sheet PROC091F_HD_CONN_PWR_SW
J8 J10 = CMP-0087785-1: CONN HEADER R/A 3POS 1.27MM; Manufacturer: Harwin; Row_Count: 1; Current_A: 1A; ContactFinish: Gold,Nickel
R66 R74 R105 R106 R115 R116 R120 R121 R123 R127 R128 R136 R139 = CMP-0086442-2: as R12 on sheet PROC091F_HD_CONN_PWR_SW
R104 R118 R122 R134 = CMP-0088002-1: as R20 on sheet PROC091F_HD_CONN_PWR_SW
R114 R117 R119 R126 = CMP-0026491-2: RES, 61.9, 1%, 0.063 W, AEC-Q200 Grade 0, 0402; Manufacturer: Vishay-Dale; Power_W: 63mW; TempCo: 100 ppm/C; Value_Code: 61R9; Value: 61.9; EIA_Code: E96; SizeX_mm: 1; SizeY_mm: 0.5; SizeZ_mm: 0.6; Value2: 0.063W; AEC Qualified: Y; VDC_V: 50V; AEC Category: Q200; AEC Grade: 0
R141 = CMP-0027745-1: as R38 on sheet PROC091F_RST_GPIOs_I2C
U11 = CMP-0050992-5: 1-Channel, 2:1 Analog Switch, DSF0006A (X2SON-6); Manufacturer: Texas Instruments; 3-State Output: No; AEC Category: Q200; AEC Qualified: N; Bits(#): 1; CompType: IC; F @ Nom Voltage(Max)(Mhz): 150; ICC @ Nom Voltage(Max)(mA): 0.01; Input Type: CMOS/TTL; Logic: True; Mux Configuration: 1：2; Output Drive (IOL/IOH)(Max)(mA): 32/-32; Output Type: CMOS; Rating: Catalog; Switch Configuration: SPDT; Technology Family: LVC; tpd @ Nom Voltage(Max)(ns): 2,1.2,0.8,0.3; VCC(Max)(V): 5.5; VCC(Min)(V): 1.65; Voltage(Nom)(V): 1.8,2.5,3.3,5
U12 U17 = CMP-0065183-3: Automotive Fault Protected CAN Transceiver With Flexible Data-Rate, DRB0008F (VSON-8); Manufacturer: Texas Instruments; Alternate PartNumber: TCAN1042HGVDRBTQ1; SizeX_mm: 3.0; CompType: IC; SizeZ_mm: 1.0; SizeArea_mm2: 9.0; SizeAreaWB_mm2: 16.0; AEC Category: Q200; AEC Qualified: Y
U13 = CMP-0067415-1: 10-Ohm Quad SPDT Analog Switch, RSV0016A (UQFN-16); Alternate Manufacturer: Texas Instruments; SizeAreaWB_mm2: 10.08; U/M: EA; SizeZ_mm: 0.55; SizeX_mm: 1.8; SizeY_mm: 2.6; SizeArea_mm2: 4.68; CompType: IC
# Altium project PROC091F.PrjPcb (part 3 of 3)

## Sheet PROC091F_Hardware.schdoc: HARDWARE
size 431 x 279 mm; Date: Not shown in title block; ApprovedBy: Not shown in title block; CheckedBy: Not shown in title block; Author: Not shown in title block; CompanyName: Not shown in title block; DrawnBy: Antony/Bala; Engineer: Not shown in title block; Organization: Not shown in title block; Address1: Not shown in title block; Address2: Not shown in title block; Address3: Not shown in title block; Address4: Not shown in title block; DocumentNumber: 12; Revision: Use project parameter SCH_Rev; SheetNumber: 12; SheetTotal: 12; PageSetup: Record=PageOptions¦CenterHorizontal=True¦CenterVertical=True¦PrintScale=1.00¦XCorrection=1.00¦YCorrection=1.00¦PrintKind=0¦BorderSize=5000000¦LeftOffset=0¦BottomOffset=0¦Orientation=2¦PaperLength=1000¦PaperWidth=1000¦Scale=100¦PaperSource=15¦PrintQuality=600¦MediaType=1¦DitherType=10¦PaperKind=Letter¦PrintScaleMode=1

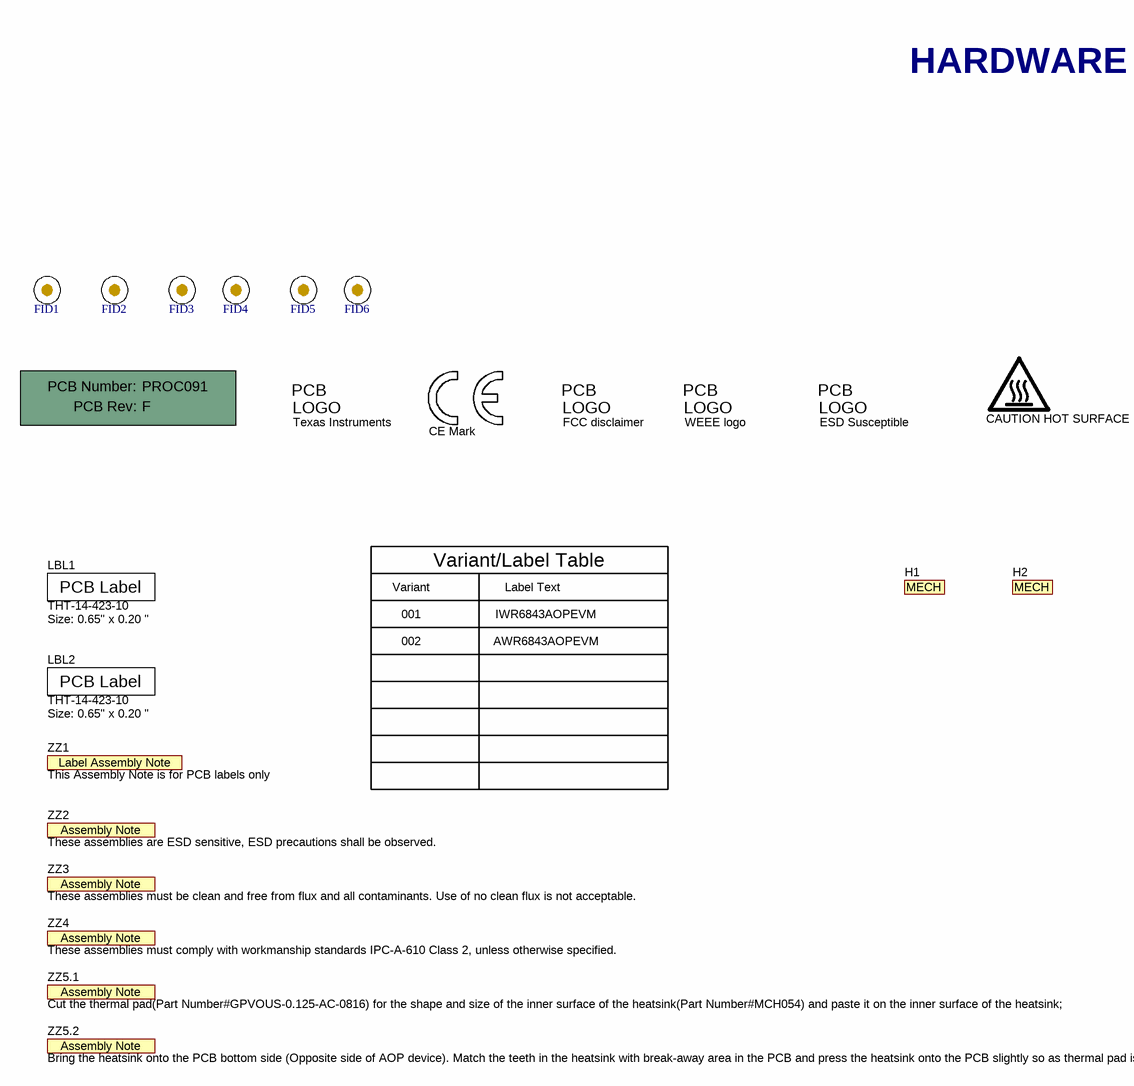
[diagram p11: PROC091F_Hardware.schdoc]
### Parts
!PCB  Printed Circuit Board  (value not drawn)  (mechanical)
CAUTION_HOT_SURFACE1  CAUTION HOT SURFACE  [IEC_HotSurface_Small]  (graphical)
ESD_Susceptible1  ESD Susceptible  [ESD_Overlay_Small]  (graphical)
FID1  Fiducial  [Fiducial6.4-20]  (value not drawn)
FID2  Fiducial  [Fiducial6.4-20]  (value not drawn)
FID3  Fiducial  [Fiducial6.4-20]  (value not drawn)
FID4  Fiducial  [Fiducial6.4-20]  (value not drawn)
FID5  Fiducial  [Fiducial6.4-20]  (value not drawn)
FID6  Fiducial  [Fiducial6.4-20]  (value not drawn)
H1  MechPart  (value not drawn)  (mechanical)
H2  MechPart  (value not drawn)  (mechanical)
LBL1  THT-14-423-10  Note: Size: 0.65" x 0.20 "  [Label_650x200]  (graphical)
LBL2  THT-14-423-10  Note: Size: 0.65" x 0.20 "  [Label_650x200]  (graphical)
Logo1  Texas Instruments  [TI_Stacked_Overlay_Small]  (graphical)
Logo2  CE Mark  [CE_Mark_5mm]  (graphical)
Logo3  FCC disclaimer  [FCC_disclaimer]  (graphical)
Logo4  WEEE logo  [WEEE_Minimum]  (graphical)
ZZ1  This Assembly Note is for PCB labels only  [AssemblyNoteLabel]  (no BOM)
ZZ2  These assemblies are ESD sensitive, ESD precautions shall be observed.  [AssemblyNote]  (no BOM)
ZZ3  These assemblies must be clean and free from flux and all contaminants. Use of no clean flux is not acceptable.  [AssemblyNote]  (no BOM)
ZZ4  These assemblies must comply with workmanship standards IPC-A-610 Class 2, unless otherwise specified.  [AssemblyNote]  (no BOM)
ZZ5.1  Cut the thermal pad(Part Number#GPVOUS-0.125-AC-0816) for the shape and size of the inner surface of the heatsink(Part Number#MCH054) and paste it on the inner surface of the heatsink;  [AssemblyNote]  (no BOM)
ZZ5.2  Bring the heatsink onto the PCB bottom side (Opposite side of AOP device). Match the teeth in the heatsink with break-away area in the PCB and press the heatsink onto the PCB slightly so as thermal pad is spread all over the area  [AssemblyNote]  (no BOM)

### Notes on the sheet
- HARDWARE
- Variant/Label Table
- Variant
- 001
- 002
- Label Text
- IWR6843AOPEVM
- AWR6843AOPEVM

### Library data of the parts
!PCB = CMP-0003618-2: Manufacturer: Any; PartNumber: PROC091
CAUTION_HOT_SURFACE1 = CMP-0074837-1: IEC 61010-1 Hot Surface Warning; Library Reference: IEC_HotSurface; SymbolCreator: a0412235
ESD_Susceptible1 = CMP-0074840-1: ESD Susceptible Symbol; Library Reference: Logo; SymbolCreator: a0412235; Lib Reference: ESD_Susceptible
FID1-FID6 = CMP-0077181-1: Fiducial mark.  There is nothing to buy or mount.
H1 = CMP-0080604-2: AOP EVM Heatsink; Manufacturer: Any; PartNumber: MCH054; Alternate PartNumber: 160018120021; CompType: Mechanical
H2 = CMP-0080604-2: Thermal Pad Pink 406.40mm x 203.20mm Rectangular Adhesive - One Side; Manufacturer: Bergquist; PartNumber: GPVOUS-0.125-AC-0816; CompType: Mechanical
LBL1 LBL2 = CMP-0003625-1: Thermal Transfer Printable Labels, 0.650" W x 0.200" H - 10,000 per roll; Manufacturer: Brady; CompType: Label
Logo1 = CMP-0074838-1: Texas Instrument Corporate Signature; SymbolCreator: a0412235; Lib Reference: TI_Logo; Library Reference: Logo
Logo2 = CMP-0074844-1: SymbolCreator: a0412235
Logo3 = CMP-0074847-1: FCC_disclaimer; Library Reference: Logo
Logo4 = CMP-0074769-1
ZZ1 = CMP-0003616-3
ZZ2 = CMP-0077236-1
ZZ3 = CMP-0077237-1
ZZ4 ZZ5.2 = CMP-0077238-1
ZZ5.1 = CMP-0077238-1: Cut the thermal pad(Part Number#GPVOUS-0.125-AC-0816) for the shape and size of the inner surface of the heatsink(Part Number#160018120021) and paste it on the inner surface of the heatsink;

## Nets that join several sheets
5V_IN: PROC091F_PMIC (12 pins), PROC091F_FLASH_USB_TO_UART (C1.2 C4.1 D1.1 R64.1), PROC091F_HD_CONN_PWR_SW (D2.1), PROC091F_RST_GPIOs_I2C (R107.1), PROC091F_CAN_INTERFACE (FL3.2 FL12.2)
5V_IN_B: PROC091F_HD_CONN_PWR_SW (C127.1 U19.6), PROC091F_ANALOG_MUX (C42.2 C122.1 FL14.2 TP4.1)
AR_1P0_RF1: PROC091F_AOP_PWR (7 pins), PROC091F_PMIC (L12.2)
AR_1P0_RF2: PROC091F_AOP_PWR (7 pins), PROC091F_PMIC (FL1.1 L14.2)
AR_1P2: PROC091F_AOP_PWR (FL6.1), PROC091F_PMIC (L13.2)
AR_VBGAP: PROC091F_AOP_IO (U2.A16), PROC091F_AOP_PWR (C69.1)
AR_VOUT_PA: PROC091F_AOP_PWR (8 pins), PROC091F_PMIC (FL1.2)
BB_1V8: PROC091F_AOP_PWR (7 pins), PROC091F_PMIC (FL8.2)
GND: PROC091F_AOP_IO (11 pins), PROC091F_AOP_PWR (116 pins), PROC091F_PMIC (26 pins), PROC091F_FLASH_USB_TO_UART (21 pins), PROC091F_HD_CONN_PWR_SW (18 pins), PROC091F_RST_GPIOs_I2C (30 pins), PROC091F_BT_DISPLAY (50 pins), PROC091F_ANALOG_MUX (17 pins), PROC091F_CAN_INTERFACE (19 pins)
PMICOUT_3V3: PROC091F_AOP_IO (12 pins), PROC091F_AOP_PWR (5 pins), PROC091F_PMIC (FL20.1 R31.2 TP5.1), PROC091F_FLASH_USB_TO_UART (15 pins), PROC091F_HD_CONN_PWR_SW (FL22.1)
VCC_BA_3V3: PROC091F_HD_CONN_PWR_SW (FL22.2 TP13.1), PROC091F_RST_GPIOs_I2C (26 pins), PROC091F_BT_DISPLAY (13 pins), PROC091F_ANALOG_MUX (C123.1 R1.2 R16.1 U15.8), PROC091F_CAN_INTERFACE (10 pins)
VCLK_1V8: PROC091F_AOP_PWR (7 pins), PROC091F_PMIC (FL9.2)
VIOIN_1V8: PROC091F_AOP_PWR (8 pins), PROC091F_PMIC (FL10.2)
ALERT: PROC091F_RST_GPIOs_I2C (R38.1 U5.3), PROC091F_BT_DISPLAY (U10.4)
AR_BSS_LOGGER: PROC091F_AOP_IO (U2.D3), PROC091F_HD_CONN_PWR_SW (RA2.2)
AR_CS1: PROC091F_AOP_IO (R9.2 U2.C2), PROC091F_CAN_INTERFACE (R139.2)
AR_CS1_60PIN: PROC091F_HD_CONN_PWR_SW (RA3.1), PROC091F_CAN_INTERFACE (U11.3)
AR_CS1_BT: PROC091F_BT_DISPLAY (U8.30), PROC091F_CAN_INTERFACE (R105.2)
AR_CS1_LCD: PROC091F_BT_DISPLAY (R76.2), PROC091F_CAN_INTERFACE (R106.2)
AR_DMM_CLK: PROC091F_AOP_IO (U2.U3), PROC091F_HD_CONN_PWR_SW (R11.1)
AR_DMM_SYNC: PROC091F_AOP_IO (U2.U4), PROC091F_HD_CONN_PWR_SW (R10.1)
AR_DP0: PROC091F_AOP_IO (U2.U7), PROC091F_HD_CONN_PWR_SW (R88.1)
AR_DP1: PROC091F_AOP_IO (U2.U6), PROC091F_HD_CONN_PWR_SW (R130.1)
AR_DP2: PROC091F_AOP_IO (U2.V5), PROC091F_HD_CONN_PWR_SW (R132.1)
AR_DP3: PROC091F_AOP_IO (U2.U5), PROC091F_HD_CONN_PWR_SW (R133.1)
AR_DP4: PROC091F_AOP_IO (U2.V3), PROC091F_HD_CONN_PWR_SW (R135.1)
AR_DP5: PROC091F_AOP_IO (U2.M1), PROC091F_HD_CONN_PWR_SW (R137.1)
AR_DP6: PROC091F_AOP_IO (U2.L2), PROC091F_HD_CONN_PWR_SW (R138.1)
AR_DP7: PROC091F_AOP_IO (U2.L1), PROC091F_HD_CONN_PWR_SW (R140.1)
AR_GPIO_0: PROC091F_AOP_IO (U2.M2), PROC091F_HD_CONN_PWR_SW (RA5.8), PROC091F_CAN_INTERFACE (R66.1)
AR_GPIO_1: PROC091F_AOP_IO (U2.L3), PROC091F_HD_CONN_PWR_SW (RA5.7), PROC091F_RST_GPIOs_I2C (R129.2)
AR_GPIO_2: PROC091F_AOP_IO (U2.K3), PROC091F_HD_CONN_PWR_SW (RA5.6), PROC091F_RST_GPIOs_I2C (LD3.1), PROC091F_CAN_INTERFACE (R115.1)
AR_HOSTINTR1: PROC091F_AOP_IO (R3.1 U2.B2), PROC091F_HD_CONN_PWR_SW (RA9.6)
AR_LVDS_0_N: PROC091F_AOP_IO (U2.N1), PROC091F_HD_CONN_PWR_SW (RA6.7)
AR_LVDS_0_P: PROC091F_AOP_IO (U2.N2), PROC091F_HD_CONN_PWR_SW (RA6.8)
AR_LVDS_1_N: PROC091F_AOP_IO (U2.P1), PROC091F_HD_CONN_PWR_SW (RA7.5)
AR_LVDS_1_P: PROC091F_AOP_IO (U2.P2), PROC091F_HD_CONN_PWR_SW (RA7.6)
AR_LVDS_CLK_N: PROC091F_AOP_IO (U2.R2), PROC091F_HD_CONN_PWR_SW (RA7.7)
AR_LVDS_CLK_P: PROC091F_AOP_IO (U2.R1), PROC091F_HD_CONN_PWR_SW (RA7.8)
AR_LVDS_FRCLK_N: PROC091F_AOP_IO (U2.T2), PROC091F_HD_CONN_PWR_SW (RA8.5)
AR_LVDS_FRCLK_P: PROC091F_AOP_IO (U2.T1), PROC091F_HD_CONN_PWR_SW (RA8.6)
AR_MCUCLKOUT: PROC091F_AOP_IO (U2.V13), PROC091F_HD_CONN_PWR_SW (RA1.1)
AR_MISO1: PROC091F_AOP_IO (U2.D1), PROC091F_CAN_INTERFACE (R121.2)
AR_MOSI1: PROC091F_AOP_IO (U2.F2), PROC091F_CAN_INTERFACE (R128.2)
AR_MSS_LOGGER: PROC091F_AOP_IO (U2.E2), PROC091F_FLASH_USB_TO_UART (R62.2), PROC091F_HD_CONN_PWR_SW (R58.1), PROC091F_BT_DISPLAY (R131.1)
AR_NERR_OUT: PROC091F_AOP_IO (R21.1 U2.U15), PROC091F_HD_CONN_PWR_SW (RA6.5)
AR_NERRIN: PROC091F_AOP_IO (R22.1 U2.U14), PROC091F_HD_CONN_PWR_SW (RA6.6)
AR_NRST: PROC091F_AOP_IO (C130.1 R59.1 TP14.1 U2.U11), PROC091F_RST_GPIOs_I2C (R108.1 U16.4)
AR_NRST_1: PROC091F_HD_CONN_PWR_SW (RA9.8), PROC091F_RST_GPIOs_I2C (R177.2 U16.1)
AR_OSC_CLKOUT: PROC091F_AOP_IO (TP17.1 U2.A14), PROC091F_HD_CONN_PWR_SW (RA1.2)
AR_PMIC_CLKOUT_SOP2: PROC091F_AOP_IO (R85.1 R103.1 U2.V10), PROC091F_HD_CONN_PWR_SW (RA1.4)
AR_QSPI_CLK: PROC091F_AOP_IO (U2.H2), PROC091F_FLASH_USB_TO_UART (R47.1)
AR_QSPI_CS: PROC091F_AOP_IO (U2.J2), PROC091F_FLASH_USB_TO_UART (R43.1 U9.1)
AR_QSPI_D0: PROC091F_AOP_IO (U2.H3), PROC091F_FLASH_USB_TO_UART (R6.1)
AR_QSPI_D1: PROC091F_AOP_IO (U2.G2), PROC091F_FLASH_USB_TO_UART (R46.1)
AR_QSPI_D2: PROC091F_AOP_IO (U2.J3), PROC091F_FLASH_USB_TO_UART (R44.1 R48.1)
AR_QSPI_D3: PROC091F_AOP_IO (U2.K2), PROC091F_FLASH_USB_TO_UART (R45.1 R49.1)
AR_RS232RX: PROC091F_AOP_IO (R5.2 U2.V16), PROC091F_FLASH_USB_TO_UART (U18.6)
AR_RS232RX_BT: PROC091F_BT_DISPLAY (R102.1), PROC091F_ANALOG_MUX (U15.4)
AR_RS232TX: PROC091F_AOP_IO (R4.2 U2.U16), PROC091F_FLASH_USB_TO_UART (U18.10)
AR_RS232TX_BT: PROC091F_BT_DISPLAY (R90.1), PROC091F_ANALOG_MUX (U15.2)
AR_SCL: PROC091F_AOP_IO (R8.1 U2.G3), PROC091F_PMIC (R32.1), PROC091F_HD_CONN_PWR_SW (RA2.4), PROC091F_RST_GPIOs_I2C (J3.2 R51.1 R67.1 R70.2), PROC091F_BT_DISPLAY (R99.2)
AR_SDA: PROC091F_AOP_IO (R7.1 U2.G1), PROC091F_PMIC (R28.1), PROC091F_HD_CONN_PWR_SW (RA2.3), PROC091F_RST_GPIOs_I2C (J3.3 R57.1 R68.1 R71.2), PROC091F_BT_DISPLAY (R101.2)
AR_SPICLK1: PROC091F_AOP_IO (R75.2 U2.D2), PROC091F_CAN_INTERFACE (R136.2)
AR_SYNC_IN: PROC091F_AOP_IO (U2.U12), PROC091F_HD_CONN_PWR_SW (RA8.8)
AR_SYNC_OUT_SOP1: PROC091F_AOP_IO (R84.1 U2.M3), PROC091F_HD_CONN_PWR_SW (RA8.7)
AR_TCK: PROC091F_AOP_IO (U2.T3), PROC091F_HD_CONN_PWR_SW (RA4.2)
AR_TDI: PROC091F_AOP_IO (U2.U9), PROC091F_HD_CONN_PWR_SW (RA4.4)
AR_TDO_SOP0: PROC091F_AOP_IO (R83.1 U2.U10), PROC091F_HD_CONN_PWR_SW (RA4.3)
AR_TMS: PROC091F_AOP_IO (U2.U8), PROC091F_HD_CONN_PWR_SW (RA4.1)
AR_WARMRST: PROC091F_AOP_IO (R23.1 U2.U13), PROC091F_HD_CONN_PWR_SW (RA1.3)
BREAK_RS232RX: PROC091F_FLASH_USB_TO_UART (TP19.1 U18.7), PROC091F_ANALOG_MUX (U15.6)
BREAK_RS232TX: PROC091F_FLASH_USB_TO_UART (TP18.1 U18.9), PROC091F_ANALOG_MUX (U15.10)
BT ENABLE: PROC091F_BT_DISPLAY (R30.1 R110.1 U8.17), PROC091F_ANALOG_MUX (S2.3)
CONN_AR_RS232RX: PROC091F_HD_CONN_PWR_SW (R14.2), PROC091F_ANALOG_MUX (U15.7)
CONN_AR_RS232TX: PROC091F_HD_CONN_PWR_SW (R12.2), PROC091F_ANALOG_MUX (U15.9)
PGOOD: PROC091F_PMIC (R31.1 R37.2), PROC091F_HD_CONN_PWR_SW (RA9.7)
PMIC_CLK: PROC091F_AOP_IO (R103.2), PROC091F_PMIC (U1.3)
SENS_INT: PROC091F_RST_GPIOs_I2C (R18.2 U7.14), PROC091F_BT_DISPLAY (R100.1)
SENS_NRST: PROC091F_RST_GPIOs_I2C (R81.2 R97.2), PROC091F_BT_DISPLAY (U10.7)
SOP0: PROC091F_AOP_IO (R159.2), PROC091F_ANALOG_MUX (S1.3)
SOP1: PROC091F_AOP_IO (R171.2), PROC091F_ANALOG_MUX (S1.4)
SPI/CAN_MUX_CTRL: PROC091F_ANALOG_MUX (S2.1), PROC091F_CAN_INTERFACE (R118.1 U13.15)
SPI_CLK1: PROC091F_HD_CONN_PWR_SW (RA3.2), PROC091F_BT_DISPLAY (R160.2 R161.1), PROC091F_CAN_INTERFACE (U13.8)
SPI_CS_MUX_CTRL: PROC091F_ANALOG_MUX (S2.2), PROC091F_CAN_INTERFACE (R104.1 U11.6)
SPI_MISO1: PROC091F_HD_CONN_PWR_SW (RA3.4), PROC091F_BT_DISPLAY (R87.1 R166.2), PROC091F_CAN_INTERFACE (U13.1)
SPI_MOSI1: PROC091F_HD_CONN_PWR_SW (RA3.3), PROC091F_BT_DISPLAY (R86.1), PROC091F_CAN_INTERFACE (U13.4)
UART_MUX_CTRL1: PROC091F_FLASH_USB_TO_UART (R19.1 U18.1 U18.5), PROC091F_ANALOG_MUX (S1.1)

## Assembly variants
001: not fitted C5 C7 C8 C9 C10 C11 C13 C15 C16 C17 C18 C38 C39 C73 C104 C114 C115 C116 C118 C119 FID1 FID2 FID3 FID4 FID5 FID6 J4 J6 R18 R20 R30 R66 R70 R71 R72 R73 R76 R77 R78 R79 R80 R81 R82 R92 R93 R96 R97 R98 R103 R106 R109 R115 R160 R166 R168 R180 R181 R182 R183 R184 R185 U4 U7 U14 Y4
002: not fitted C5 C7 C8 C9 C10 C11 C13 C15 C16 C17 C18 C38 C39 C73 C104 C114 C115 C116 C118 C119 FID1 FID2 FID3 FID4 FID5 FID6 J4 J6 R18 R20 R30 R66 R70 R71 R72 R73 R76 R77 R78 R79 R80 R81 R82 R92 R93 R96 R97 R98 R103 R106 R109 R115 R160 R166 R168 R180 R181 R182 R183 R184 R185 U4 U7 U14 Y4; alternate parts U2 -> CMP-0860942-3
